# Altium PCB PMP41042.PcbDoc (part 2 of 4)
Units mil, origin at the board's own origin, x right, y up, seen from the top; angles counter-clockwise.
Board outline 9847.6 x 4445 mil, 6 copper layers (Top Layer, Layer 1, Layer 2, Layer 3, Layer 4, Bottom Layer), stack 32.112 mil thick; 329 components, 129 nets, 1246 pads, 863 vias.
Unrouted connection lines stored in the file: 6.

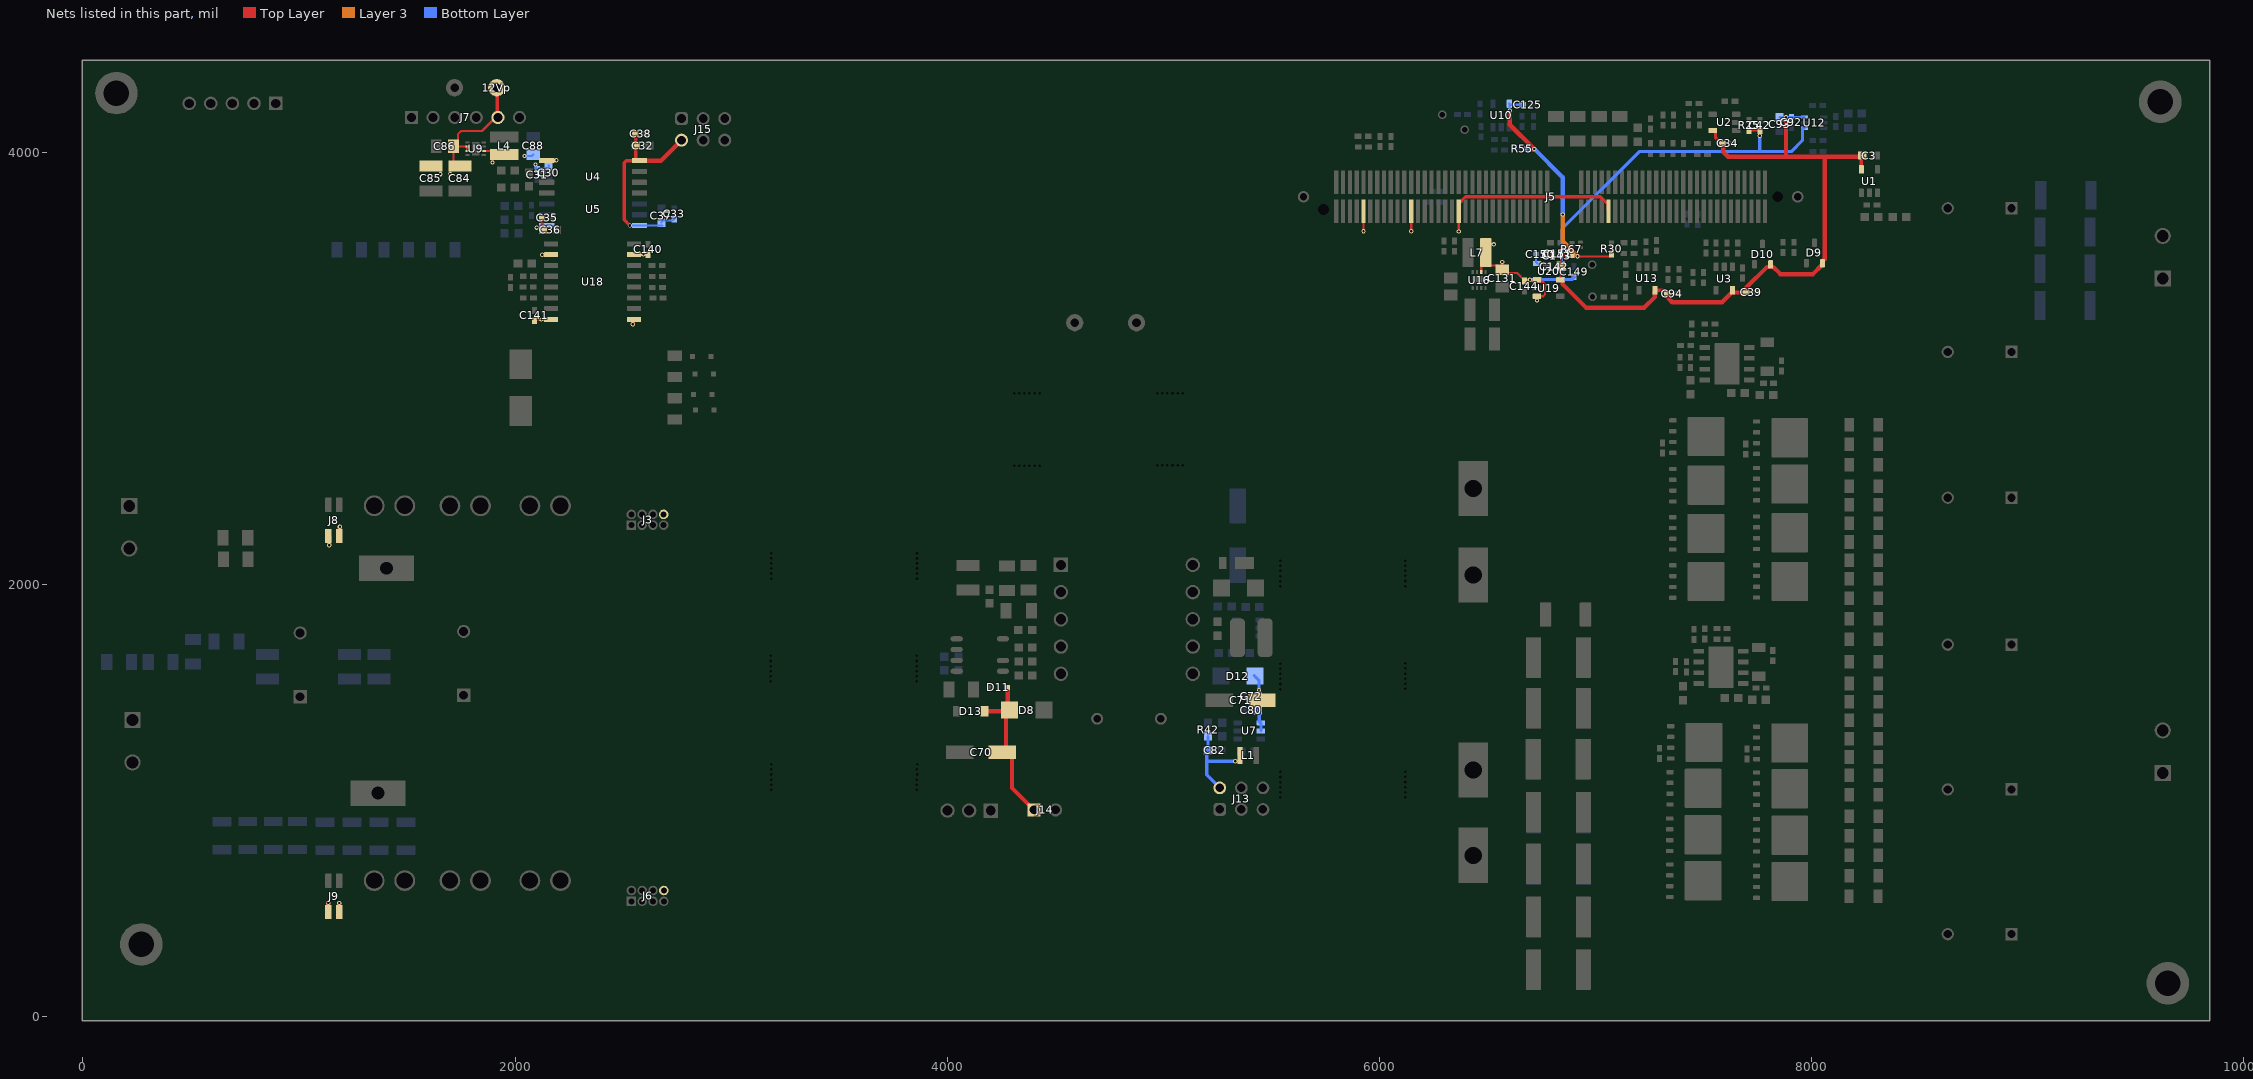
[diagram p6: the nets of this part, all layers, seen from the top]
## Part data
12Vp 12Vs: library part CMP-0055137-1, "Test Point, Miniature, Red, TH", Color=Red, Manufacturer=Keystone, Supplier Part Number 1=36-5000-ND
C1 C5 C9 C15 C90 C113 C118: library part CMP-0034099-1, "Cap Ceramic 10nF 1000V C0G 5% Pad SMD 1210 +125°C Automotive T/R", Manufacturer=TDK, Operating Temperature Range="-55°C to +125°C", TempCo=30ppm/°C, Temperature Characteristic=C0G, Tolerance_%=0.05%, ValueDisplayed=10nF
C2 C4 C6 C7 C10 C14 C16 C17 C19 C21 C23 C24 C27 C28: library part CMP-0097370-1, "0.3 µF ±5% 250V Ceramic Capacitor C0G, NP0 Stacked SMD, 2 J-Lead", Digikey Part Number=445-175448-1-ND, Manufacturer=TDK, Mouser Part Number=810-CKG57NCG2E304J50, Operating Temperature Range="-55°C to +125°C", TempCo=30ppm/°C, Temperature Characteristic=C0G, Tolerance_%=5%, ValueDisplayed=300nF
C3: library part CMP-0007378-5, "CAP, CERM, 0.1 uF, 16 V, +/- 10%, X7R, 0603", Cap_Case=0603, Manufacturer=MuRata, Supplier Part Number 1=490-1532-1-ND, TempCo=X7R, Tolerance_%=10%, Value1=Unknown, Value2=16V, ValueDisplayed=0.1uF
C8 C101: library part CMP-0009975-3, "CAP, AL, 150 uF, 450 V, +/- 20%, TH", Cap_Case=18x45mm, Manufacturer=Rubycon, Supplier Part Number 1=1189-1353-ND, Tolerance_%=20%, Value1=Unknown, Value2=450V, ValueDisplayed=150uF
C11 C12 C13: library part CMP-0009140-2, "CAP, CERM, 0.1 uF, 630 V, +/- 10%, X7R, AEC-Q200 Grade 1, 1210", Cap_Case=1210, Manufacturer=TDK, Supplier Part Number 1=445-7116-1-ND, TempCo=X7R, Tolerance_%=10%, Value1=Unknown, Value2=630V, ValueDisplayed=0.1uF
C18: library part CMP-0006470-1, "CAP, CERM, 470 pF, 50 V, +/- 5%, C0G/NP0, 0402", Cap_Case=0402, Manufacturer=MuRata, Supplier Part Number 1=490-1297-1-ND, TempCo=C0G/NP0, Tolerance_%=5%, Value1=Unknown, Value2=50V, ValueDisplayed=470pF
C20 C22: library part CMP-0097363-1, "Multilayer Ceramic Capacitors 100nF ±5% 250V C0G SMD 1812", Manufacturer=TDK, Operating Temperature Range="-55°C to +125°C", TempCo=30ppm/°C, Temperature Characteristic=C0G, Tolerance_%=0.05%, ValueDisplayed=100nF
C25 C42: library part CMP-0006352-2, "CAP, CERM, 0.01 uF, 25 V, +/- 10%, X7R, 0402", Cap_Case=0402, Manufacturer=MuRata, Supplier Part Number 1=490-6043-2-ND, TempCo=X7R, Tolerance_%=10%, Value1=Unknown, Value2=25V, ValueDisplayed=0.01uF
C26 C109 C139 C145 C146 C147 C148: library part CMP-0006408-1, "CAP, CERM, 10 pF, 50 V, +/- 5%, C0G/NP0, 0402", Cap_Case=0402, Manufacturer=MuRata, Supplier Part Number 1=81-GRM1555C1H100JA1D, TempCo=C0G/NP0, Tolerance_%=5%, Value1=Unknown, Value2=50V, ValueDisplayed=10pF
C29 C43 C45: library part CMP-0860554-1, "CAP, CERM, 0.01 µF, 16 V,+/- 10%, X7R, 0402", Cap_Case=0402, Manufacturer=Yageo, TempCo=X7R, Tolerance_%=10%, Value2=16V, ValueDisplayed=0.01µF
C30 C32 C93: library part CMP-0079607-1, "CAP, CERM, 1 µF, 16 V,+/- 10%, X7R, AEC-Q200 Grade 1, 0603", Cap_Case=0603, Manufacturer=TDK, Supplier Part Number 1=445-12539-1-ND, TempCo=X7R, Tolerance_%=10%, Value2=16V, ValueDisplayed=1µF
C31 C33 C34 C35 C38 C39 C92 C94 C103 C110 C112 C114 C125: library part CMP-0006659-2, "CAP, CERM, 0.1 uF, 25 V, +/- 10%, X7R, 0402", Cap_Case=0402, Manufacturer=MuRata, Supplier Part Number 1=490-10698-1-ND, TempCo=X7R, Tolerance_%=10%, Value1=Unknown, Value2=25V, ValueDisplayed=0.1uF
C36 C37 C102 C115: library part CMP-0064936-4, "CAP, CERM, 4.7 uF, 16 V,+/- 10%, X7R, 0603", Cap_Case=0603, Manufacturer=MuRata, TempCo=X7R, Tolerance_%=10%, Value1=Unknown, Value2=16V, ValueDisplayed=4.7uF
C40: library part CMP-0079721-1, "CAP, CERM, 0.01 µF, 25 V,+/- 10%, X7R, 0603", Cap_Case=0603, Manufacturer="Presidio Components", TempCo=X7R, Tolerance_%=10%, Value2=25V, ValueDisplayed=0.01µF
C41 C44 C46 C47 C48 C49 C50 C51 C52 C53 C54 C55 C56 C57 C60 C76 C77 C87 C163 C164 C186 C187 C188 C189 C190: library part CMP-0008971-1, "CAP, CERM, 2.2 uF, 100 V, +/- 10%, X7R, 1206_190", Cap_Case=1206, Manufacturer=MuRata, Supplier Part Number 1=490-7209-1-ND, TempCo=X7R, Tolerance_%=10%, Value1=Unknown, Value2=100V, ValueDisplayed=2.2uF
C58 C59 C61 C62 C63 C64: library part CMP-0097417-1, "1000 µF 80 V Aluminum Electrolytic Capacitors Radial, Can 27mOhm @ 100kHz 2000 Hrs @ 135°C", Digikey Part Number=565-EGPD800ELL102ML35H-ND, Leakage Current=2400uA, Manufacturer="United Chemi-Con", Mouser Part Number=661-EGPD800E102ML35H, Operating Temperature Range="-40°C to +135°C", Tolerance_%=20%, ValueDisplayed=1000uF
C65: library part CMP-0009608-4, "CAP, CERM, 47 pF, X1 250 VAC/Y1 300 VAC, +/- 10%, B, TH", Cap_Case=7x5x10mm, Manufacturer=MuRata, Supplier Part Number 1=490-9495-1-ND, TempCo=B, Tolerance_%=10%, Value1=Unknown, ValueDisplayed=47pF
C66: library part CMP-0008910-2, "CAP, CERM, 0.01 uF, 630 V, +/- 10%, X7R, 1206", Cap_Case=1206, Manufacturer=MuRata, Supplier Part Number 1=490-3512-1-ND, TempCo=X7R, Tolerance_%=10%, Value1=Unknown, Value2=630V, ValueDisplayed=0.01uF
C67: library part CMP-0009092-1, "CAP, CERM, 0.1 uF, 500 V, +/- 10%, X7R,", Cap_Case=1210, Manufacturer=Kemet, Supplier Part Number 1=399-6478-1-ND, TempCo=X7R, Tolerance_%=10%, Value1=Unknown, Value2=500V, ValueDisplayed=0.1uF
C68: library part CMP-0012117-3, "CAP, Aluminum Polymer, 100 uF, 25 V, +/- 20%, 0.024 ohm, 8.0x7.0mm SMD", Manufacturer=Panasonic, Tolerance_%=20%, Value1="0.024 ohm", Value2=25V, ValueDisplayed=100uF
C69 C72: library part CMP-0007404-4, "CAP, CERM, 0.1 uF, 25 V, +/- 10%, X7R, 0603", Cap_Case=0603, Manufacturer=MuRata, Supplier Part Number 1=490-16477-2-ND, TempCo=X7R, Tolerance_%=10%, Value1=Unknown, Value2=25V, ValueDisplayed=0.1uF
C70: library part CMP-0010738-1, "CAP, AL, 220 uF, 25 V, +/- 20%, 0.16 ohm, AEC-Q200 Grade 2, SMD", Cap_Case=6.3x7.7mm, Manufacturer=Panasonic, Supplier Part Number 1=PCE5009CT-ND, Tolerance_%=20%, Value1="0.16 ohm", Value2=25V, ValueDisplayed=220uF
C71: library part CMP-0084632-1, "CAP, AL, 470 µF, 10 V, +/- 20%, 0.16 ohm, AEC-Q200 Grade 2, SMD", Cap_Case=6.6x6.6x8mm, Manufacturer=Panasonic, Tolerance_%=20%, Value1="0.16 ohm", Value2=10V, ValueDisplayed=470µF
C73: library part CMP-0008646-2, "CAP, CERM, 47 uF, 25 V, +/- 20%, JB, 1206", Cap_Case=1206, Manufacturer=TDK, Supplier Part Number 1=445-11717-1-ND, TempCo=JB, Tolerance_%=20%, Value1=Unknown, Value2=25V, ValueDisplayed=47uF
C74: library part CMP-0006840-4, "CAP, CERM, 100 pF, 50 V, +/- 5%, C0G/NP0, 0603", Cap_Case=0603, Manufacturer=Kemet, Supplier Part Number 1=1414602, TempCo=C0G/NP0, Tolerance_%=5%, Value1=Unknown, Value2=50V, ValueDisplayed=100pF
C75: library part CMP-0007224-4, "CAP, CERM, 56 pF, 50 V, +/- 5%, C0G/NP0, 0603", Cap_Case=0603, Manufacturer=MuRata, Supplier Part Number 1=490-1421-1-ND, TempCo=C0G/NP0, Tolerance_%=5%, Value1=Unknown, Value2=50V, ValueDisplayed=56pF
C78 C79: library part CMP-0007039-5, "CAP, CERM, 0.1 uF, 25 V, +/- 10%, X7R, 0603", Cap_Case=0603, Manufacturer=TDK, Supplier Part Number 1=445-1316-1-ND, TempCo=X7R, Tolerance_%=10%, Value1=Unknown, Value2=25V, ValueDisplayed=0.1uF
C80 C81: library part CMP-0007347-1, "CAP, CERM, 4.7 uF, 25 V, +/- 10%, X5R, 0603", Cap_Case=0603, Manufacturer=MuRata, Supplier Part Number 1=490-7203-1-ND, TempCo=X5R, Tolerance_%=10%, Value1=Unknown, Value2=25V, ValueDisplayed=4.7uF
C82: library part CMP-0007005-1, "CAP, CERM, 22 uF, 10 V, +/- 20%, X5R, 0603", Cap_Case=0603, Manufacturer=TDK, Supplier Part Number 1=445-9077-1-ND, TempCo=X5R, Tolerance_%=20%, Value1="0.00371 ohm", Value2=10V, ValueDisplayed=22uF
C83: library part CMP-0007501-4, "CAP, CERM, 10 uF, 25 V, +/- 20%, X5R, 0603", Cap_Case=0603, Manufacturer=MuRata, Supplier Part Number 1=490-12323-1-ND, TempCo=X5R, Tolerance_%=20%, Value1=Unknown, Value2=25V, ValueDisplayed=10uF
C84 C85 C128 C129: library part CMP-0009211-2, "CAP, CERM, 47 uF, 16 V, +/- 10%, X5R, 1210", Cap_Case=1210, Manufacturer=MuRata, Supplier Part Number 1=GRM32ER61C476KE15L-ND, TempCo=X5R, Tolerance_%=10%, Value1=Unknown, Value2=16V, ValueDisplayed=47uF
C86 C130: library part CMP-0007728-2, "CAP, CERM, 1 uF, 25 V, +/- 10%, X7R, 0805", Cap_Case=0805, Manufacturer=Kemet, Supplier Part Number 1=399-8004-1-ND, TempCo=X7R, Tolerance_%=10%, Value1=Unknown, Value2=25V, ValueDisplayed=1uF
C88 C131: library part CMP-0085852-1, "CAP, CERM, 22 µF, 16 V,+/- 10%, X5R, 0805", Cap_Case=0805, Manufacturer="Samsung Electro-Mechanics", TempCo=X5R, Tolerance_%=10%, Value2=16V, ValueDisplayed=22µF
C89 C104 C117 C133: library part CMP-0006201-2, "CAP, CERM, 0.1 uF, 16 V, +/- 10%, X7R, 0402", Cap_Case=0402, Manufacturer=AVX, Supplier Part Number 1=478-7888-1-ND, TempCo=X7R, Tolerance_%=10%, Value1=Unknown, Value2=16V, ValueDisplayed=0.1uF
C91 C124: library part CMP-0006448-1, "CAP, CERM, 2.2 pF, 50 V, +/- 5%, C0G/NP0, 0402", Cap_Case=0402, Manufacturer=MuRata, Supplier Part Number 1=81-GRM1555C1H2R2CA1D, TempCo=C0G/NP0, Tolerance_%=5%, Value1=Unknown, Value2=50V, ValueDisplayed=2.2pF
C95 C132: library part CMP-0860561-1, "CAP, CERM, 0.01 µF, 25 V,+/- 10%, X7R, 0402", Cap_Case=0402, Manufacturer="Samsung Electro-Mechanics", TempCo=X7R, Tolerance_%=10%, Value2=25V, ValueDisplayed=0.01µF
C96: library part CMP-0006666-2, "CAP, CERM, 0.033 uF, 25 V, +/- 10%, X7R, 0402", Cap_Case=0402, Manufacturer=MuRata, Supplier Part Number 1=490-3253-1-ND, TempCo=X7R, Tolerance_%=10%, Value1=Unknown, Value2=25V, ValueDisplayed=0.033uF
C97: library part CMP-0006320-2, "CAP, CERM, 470 pF, 50 V, +/- 10%, X7R, AEC-Q200 Grade 1, 0402", Cap_Case=0402, Manufacturer=TDK, Supplier Part Number 1=445-6888-1-ND, TempCo=X7R, Tolerance_%=10%, Value1="4.96489 ohm", Value2=50V, ValueDisplayed=470pF
C98 C107 C108 C116 C122 C123 C126 C127 C134 C135: library part CMP-0006233-1, "CAP, CERM, 100 pF, 25 V, +/- 5%, C0G/NP0, 0402", Cap_Case=0402, Manufacturer=Kemet, Supplier Part Number 1=399-1022-1-ND, TempCo=C0G/NP0, Tolerance_%=5%, Value1=Unknown, Value2=25V, ValueDisplayed=100pF
C99 C100 C111: library part CMP-0860560-1, "CAP, CERM, 1000 pF, 50 V,+/- 10%, X7R, 0402", Cap_Case=0402, Manufacturer="Samsung Electro-Mechanics", TempCo=X7R, Tolerance_%=10%, Value2=50V, ValueDisplayed=1000pF
C105 C120: library part CMP-0078499-1, "CAP, CERM, 4.7 µF, 100 V,+/- 20%, X7S, 1206", Cap_Case=1206, Manufacturer=AVX, Supplier Part Number 1=478-8719-1-ND, TempCo=X7S, Tolerance_%=20%, Value2=100V, ValueDisplayed=4.7µF
C106 C121: library part CMP-0006618-1, "CAP, CERM, 0.1 uF, 100 V, +/- 10%, X5R, 0402", Cap_Case=0402, Manufacturer=MuRata, Supplier Part Number 1=490-10458-1-ND, TempCo=X5R, Tolerance_%=10%, Value1=Unknown, Value2=100V, ValueDisplayed=0.1uF
C119: library part CMP-0034099-1, "Cap Ceramic 18nF 1000V C0G 5% Pad SMD 1210 +125°C Automotive T/R", Manufacturer=TDK, Operating Temperature Range="-55°C to +125°C", Part Number=CGA6P1C0G3A103J250AC, TempCo=30ppm/°C, Temperature Characteristic=C0G, Tolerance_%=0.05%, ValueDisplayed=10nF
C140 C141: library part CMP-0006297-2, "CAP, CERM, 0.1 uF, 50 V, +/- 10%, X7R, 0402", Alternate Manufacturer="Wurth Elektronik", Alternate PartNumber=885012205037, Cap_Case=0402, Manufacturer=TDK, Supplier Part Number 1=445-5932-1-ND, TempCo=X7R, Tolerance_%=10%, Value1="0.039064 ohm", Value2=50V, ValueDisplayed=0.1uF
C142: library part CMP-0007365-1, "CAP, CERM, 1 uF, 10 V, +/- 10%, X7R, 0603", Cap_Case=0603, Manufacturer=MuRata, Supplier Part Number 1=490-3899-1-ND, TempCo=X7R, Tolerance_%=10%, Value1="0.011 ohm", Value2=10V, ValueDisplayed=1uF
C143 C150 C151: library part GRM155R70J104KA01D, "CAP, CERM, 0.1uF, 6.3V, +/-10%, X7R, 0402", Cap_Case=0402, Manufacturer=Yageo, TempCo=X7R, Tolerance_%=10, Value1=Unknown, Value2=6.3V, ValueDisplayed=0.1uF
C144 C149: library part CMP-0080610-1, "CAP, CERM, 0.1 µF, 25 V,+/- 10%, X7R, AEC-Q200 Grade 1, 0402", Cap_Case=0402, Manufacturer=TDK, Supplier Part Number 1=445-6902-1-ND, TempCo=X7R, Tolerance_%=10%, Value2=25V, ValueDisplayed=0.1µF
D1 D2 D3 D4: library part CMP-0029006-2, "Diode, Ultrafast, 100 V, 0.25 A, SOD-323", Manufacturer=Nexperia, Value1=0.25A, Value2=1.4V
D5: library part CMP-0028371-1, "Diode, Schottky, 100 V, 1 A, SMA", Manufacturer="Diodes Inc.", Supplier Part Number 1=B1100-FDICT-ND, Value1=1A, Value2=0.79V
D6: library part CMP-0077074-2, "Diode, Superfast Rectifier, 600 V, 1 A, 3.5x1.6mm", Manufacturer=Toshiba, Value1=1A, Value2=1.7V
D7: library part CMP-0005415-4, "Diode, Zener, 24 V, 1 W, PowerDI123", Manufacturer="Diodes Inc.", Power_W=1W
D8: library part CMP-0028391-2, "Diode, Schottky, 70 V, 1 A, SMA", Manufacturer="Diodes Inc.", Value1=1A, Value2=0.79V
D9 D10: library part CMP-0028456-1, "Diode, Schottky, 30 V, 0.2 A, SOT-23", Manufacturer="Diodes Inc.", Supplier Part Number 1=BAT54S-FDICT-ND, Value1=0.2A, Value2=0.65V
D11: library part CMP-0029006-1, "Diode, Ultrafast, 100 V, 0.25 A, SOD-323", Manufacturer=Nexperia, Supplier Part Number 1=568-5003-1-ND, Value1=0.25A, Value2=1.4V
D12: library part CMP-0028405-2, "Diode, Schottky, 50 V, 2 A, SMA", Manufacturer="Diodes Inc.", Value1=2A, Value2=0.7V
D13: library part CMP-0005747-4, "Diode, Zener, 18 V, 700 mW, SOD-123", Manufacturer=Toshiba, Power_W=700mW, Value1=0.7W
DGND PGND: library part CMP-0055138-1, "Test Point, Miniature, Black, TH", Color=Black, Manufacturer=Keystone, Supplier Part Number 1=36-5001-ND
GaN_SW1 GaN_SW1 GaN_SW2 GaN_SW2 HVBUS HVBUS HVBUS1 HVBUS2 PGND PGND PGND1 PGND2: library part CMP-0055026-1, Manufacturer=Mill-Max, Supplier Part Number 1=0312-015153427100-ND
J1 J2 J10 J11: library part CMP-0054978-1, "Therminal Block, 5 mm, 2-pole, Tin, TH", Manufacturer="TE Connectivity", Supplier Part Number 1=A98355-ND
J3 J6: library part CMP-0097755-1, "Conn Socket Strip SKT 8 POS 1.27mm Solder ST Thru-Hole", Current_A=1A, Manufacturer=Harwin, Operating Temperature Range="-40°C to +105°C"
J4: library part CMP-0054800-1, "Header, 2.54 mm, 5x1, Gold, R/A, TH", Color=Black, Manufacturer="Wurth Elektronik", Supplier Part Number 1=732-5338-ND
J5: library part CMP-0003814-2, "C2000 controlCARD-120HSEC connector, SMT", Manufacturer=Samtec
J7: library part CMP-0075621-1, "Receptacle, 6x1, 2.54mm, Tin, TH", Color=Black, Current_A=5.7A, Manufacturer=Samtec, Supplier Part Number 1=SAM1213-06-ND
J8 J9: library part CMP-0097647-1, Current_A=2.9A, Digikey Part Number=SAM1226-02-ND, Manufacturer=Samtec, Mouser Part Number=200-FLE10201GDV, Octopart Part Number=93aa5aa4310c4c6d, Operating Temperature Range="-55°C to +125°C"
J12: library part CMP-0054704-1, "Header, 100mil, 3x1, Tin, R/A, TH", Color=Black, Current_A=3A, Manufacturer="Sullins Connector Solutions", Supplier Part Number 1=S1112E-03-ND, Voltage_V=1.8kV
J13: library part CMP-0077741-2, "Header, 2.54mm, 3x2, Gold, R/A, TH", Color=Black, Current_A=3A, Manufacturer=Molex, Supplier Part Number 1=WM50030-06-ND, Voltage_V=350V
J14: library part CMP-0054712-1, "Header, 2.54 mm, 2x1, Tin, R/A, TH", Color=Black, Current_A=3A, Manufacturer="Sullins Connector Solutions", Supplier Part Number 1=S1112E-02-ND, Voltage_V=1.8kV
J15: library part CMP-0082513-1, "Receptacle, 2.54mm, 3x2, Gold, TH", Color=Black, Current_A=3A, Manufacturer="Sullins Connector Solutions", Supplier Part Number 1=S7106-ND, Voltage_V=250V
L1: library part CMP-0063086-1, "Inductor, Wirewound, Ferrite, 10 uH, 0.68 A, 0.46 ohm, SMD", Manufacturer="Würth Elektronik", Value1="0.843 ohm", Value2=0.6A, ValueDisplayed=10uH
L3: library part CMP-0064687-1, "Inductor, Wirewound, Ferrite, 18 uH, 1.1 A, 0.225 ohm, AEC-Q200 Grade 1, SMD", Manufacturer="Wurth Elektronik", Supplier Part Number 1=732-6815-1-ND, Value1="0.225 ohm", Value2=1.1A, ValueDisplayed=18uH
L4 L7: library part CMP-0087867-1, "2.2µH Shielded Molded Inductor 2.4A 67mOhm Max 2-SMD", Manufacturer="Wurth Electronics"
Q1 Q2 Q3 Q4 Q5 Q6 Q7 Q8 Q9 Q10 Q11 Q12 Q13 Q14 Q15 Q16: library part CMP-0000915-1, "MOSFET, N-CH, 80 V, 100 A, DNK0008A (VSON-CLIP-8)", Alternate Manufacturer=None, Manufacturer="Texas Instruments", Supplier Part Number 1=296-37194-1-ND, Value2="48 nC"
R1 R2 R4 R7: library part CMP-0016568-2, "RES, 100 k, 1%, 0.25 W, 1206", Manufacturer=Vishay-Dale, Power_W=250mW, Supplier Part Number 1=541-100KFCT-ND, TempCo="100 ppm/C", Tolerance_%=1%, Value2=0.25W, Value_Code=100k
R3: library part CMP-0022438-1, "RES, 47.0 k, 1%, 0.1 W, AEC-Q200 Grade 0, 0603", Manufacturer=Vishay-Dale, Power_W=100mW, Supplier Part Number 1=541-47.0KHCT-ND, TempCo="100 ppm/C", Tolerance_%=1%, Value2=0.1W, Value_Code=47k0, ValueDisplayed=47.0k
R5 R27: library part CMP-0022983-5, "RES, 2.10 k, 1%, 0.1 W, 0603", Manufacturer=Yageo, Power_W=100mW, Supplier Part Number 1=311-2.10KHRCT-ND, TempCo="100 ppm/C", Tolerance_%=1%, Value2=0.1W, Value_Code=2k10, ValueDisplayed=2.10k
R6 R74: library part CMP-0025884-2, "RES, 0, 5%, 0.125 W, 0603", Manufacturer=Vishay/Beyschlag, Power_W=125mW, Supplier Part Number 1=MCT0603-0.0-ZZCT-ND, TempCo=ppm/C, Tolerance_%=5%, Value2=0.125W, Value_Code=0000, ValueDisplayed=0
R8 R9: library part CMP-0078823-1, "RES, 0.004, 1%, 1 W, AEC-Q200 Grade 0, 1206", Manufacturer=Bourns, Power_W=1W, TempCo="50 ppm/C", Tolerance_%=1%, Value_Code=4L000, ValueDisplayed=0.004
R10 R11 R12 R13: library part CMP-0018320-1, "RES, 47.0, 1%, 0.25 W, 1206", Manufacturer="Yageo America", Power_W=250mW, Supplier Part Number 1=311-47.0FRCT-ND, TempCo="100 ppm/C", Tolerance_%=1%, Value2=0.25W, Value_Code=47R0, ValueDisplayed=47.0
R14 R19 R21 R25: library part CMP-0026739-1, "RES, 4.70 k, 1%, 0.0625 W, 0402", Manufacturer="Yageo America", Power_W=62.5mW, Supplier Part Number 1=311-4.7KLRCT-ND, TempCo="100 ppm/C", Tolerance_%=1%, Value2=0.0625W, Value_Code=4k70, ValueDisplayed=4.70k
R15 R17: library part CMP-0017437-1, "RES, 200 k, 1%, 0.25 W, 1206", Manufacturer=Panasonic, Power_W=250mW, Supplier Part Number 1=P200KFCT-ND, TempCo="100 ppm/C", Tolerance_%=1%, Value2=0.25W, Value_Code=200k
R16 R29: library part CMP-0026769-2, "RES, 10.0 k, 0.5%, 0.063 W, AEC-Q200 Grade 0, 0402", Manufacturer=Vishay-Dale, Power_W=63mW, Supplier Part Number 1=541-10KAVCT-ND, TempCo="50 ppm/C", Tolerance_%=0.5%, Value2=0.063W, Value_Code=10k0, ValueDisplayed=10.0k
R18 R24 R70 R72: library part CMP-0022003-4, "RES, 10.0, 1%, 0.1 W, AEC-Q200 Grade 0, 0603", Manufacturer=Vishay-Dale, Power_W=100mW, Supplier Part Number 1=541-10.0HCT-ND, TempCo="100 ppm/C", Tolerance_%=1%, Value2=0.1W, Value_Code=10R0, ValueDisplayed=10.0
R20: library part CMP-0017285-1, "RES, 100 k, 1%, 0.25 W, 1206", Manufacturer=Panasonic, Power_W=250mW, Supplier Part Number 1=P100KFCT-ND, TempCo="100 ppm/C", Tolerance_%=1%, Value2=0.25W, Value_Code=100k
R22 R28: library part CMP-0025697-2, "RES, 0, 5%, 0.1 W, 0603", Manufacturer=Vishay-Dale, Power_W=100mW, Supplier Part Number 1=541-0.0GCT-ND, TempCo="200 ppm/C", Tolerance_%=5%, Value2=0.1W, Value_Code=0000, ValueDisplayed=0
R23 R26: library part CMP-0026514-2, "RES, 6.34 k, 1%, 0.063 W, AEC-Q200 Grade 0, 0402", Manufacturer=Vishay-Dale, Power_W=63mW, Supplier Part Number 1=541-6.34KLCT-ND, TempCo="100 ppm/C", Tolerance_%=1%, Value2=0.063W, Value_Code=6k34, ValueDisplayed=6.34k
R30 R31 R55 R58: library part CMP-0025958-1, "RES, 10.0 k, 1%, 0.063 W, 0402", Manufacturer=Vishay-Dale, Power_W=63mW, Supplier Part Number 1=541-10.0KLCT-ND, TempCo="100 ppm/C", Tolerance_%=1%, Value2=0.063W, Value_Code=10k0, ValueDisplayed=10.0k
R32: library part CMP-0018591-3, "RES, 150 k, 5%, 0.25 W, 1206", Manufacturer=Vishay-Dale, Power_W=250mW, Supplier Part Number 1=541-150KECT-ND, TempCo="200 ppm/C", Tolerance_%=5%, Value2=0.25W, Value_Code=150k
R33: library part CMP-0025720-4, "RES, 15, 5%, 0.1 W, AEC-Q200 Grade 0, 0603", Manufacturer=Vishay-Dale, Power_W=100mW, Supplier Part Number 1=541-15GCT-ND, TempCo="200 ppm/C", Tolerance_%=5%, Value2=0.1W, Value_Code=15R0, ValueDisplayed=15
R34: library part CMP-0023166-5, "RES, 51.1 k, 1%, 0.1 W, 0603", Manufacturer=Yageo, Power_W=100mW, Supplier Part Number 1=311-51.1KHRCT-ND, TempCo="100 ppm/C", Tolerance_%=1%, Value2=0.1W, Value_Code=51k1, ValueDisplayed=51.1k
R35: library part CMP-0025885-5, "RES, 0, 5%, 0.1 W, 0603", Manufacturer=Yageo, Power_W=100mW, Supplier Part Number 1=311-0.0GRCT-ND, TempCo="200 ppm/C", Tolerance_%=5%, Value2=0.1W, Value_Code=0000, ValueDisplayed=0
R36 R37 R47 R48: library part CMP-0022711-2, "RES, 2.20, 1%, 0.1 W, 0603", Manufacturer=Vishay-Dale, Power_W=100mW, Supplier Part Number 1=541-5.1GCT-ND, TempCo="200 ppm/C", Tolerance_%=5%, Value2=0.1W, Value_Code=5R10, ValueDisplayed=5.1
R38 R39 R51 R52: library part CMP-0026659-1, "RES, 100 k, 1%, 0.1 W, 0402", Manufacturer=Panasonic, Power_W=100mW, TempCo="100 ppm/C", Tolerance_%=1%, Value2=0.1W, Value_Code=100k
R40: library part CMP-0022945-5, "RES, 24.0 k, 1%, 0.1 W, 0603", Manufacturer=Yageo, Power_W=100mW, Supplier Part Number 1=311-24.0KHRCT-ND, TempCo="100 ppm/C", Tolerance_%=1%, Value2=0.1W, Value_Code=24k0, ValueDisplayed=24.0k
R41: library part CMP-0025080-1, "RES, 2.00 k, 0.5%, 0.1 W, 0603", Manufacturer="Yageo America", Power_W=100mW, TempCo="50 ppm/C", Tolerance_%=0.5%, Value2=0.1W, Value_Code=2k00, ValueDisplayed=2.00k
R42: library part CMP-0022632-1, "RES, 88.7 k, 1%, 0.1 W, 0603", Manufacturer=Vishay-Dale, Power_W=100mW, Supplier Part Number 1=541-88.7KHCT-ND, TempCo="100 ppm/C", Tolerance_%=1%, Value2=0.1W, Value_Code=88k7, ValueDisplayed=88.7k
R43: library part CMP-0023982-2, "RES, 243 k, 0.1%, 0.1 W, 0603", Manufacturer="Yageo America", Power_W=100mW, TempCo="25 ppm/C", Tolerance_%=0.1%, Value2=0.1W, Value_Code=243k
R44 R45: library part CMP-0022220-1, "RES, 22.1 k, 1%, 0.1 W, 0603", Manufacturer=Vishay-Dale, Power_W=100mW, Supplier Part Number 1=541-22.1KHCT-ND, TempCo="100 ppm/C", Tolerance_%=1%, Value2=0.1W, Value_Code=22k1, ValueDisplayed=22.1k
R46 R49 R50 R54: library part CMP-0015817-2, "RES, 0.0005, 1%, 2 W, 2512", Manufacturer="Stackpole Electronics Inc", Power_W=3W, TempCo=ppm/C, Tolerance_%=1%, Value2=2W, Value_Code=1L000, ValueDisplayed=0.0005
R53: library part CMP-0026883-3, "RES, 24 k, 5%, 0.063 W, AEC-Q200 Grade 0, 0402", Manufacturer=Vishay-Dale, Power_W=63mW, Supplier Part Number 1=541-10.0KLCT-ND, TempCo="100 ppm/C", Tolerance_%=1%, Value2=0.063W, Value_Code=10k0, ValueDisplayed=10.0k
R56 R66: library part CMP-0026657-1, "RES, 1.00 k, 1%, 0.1 W, 0402", Manufacturer=Panasonic, PartNumber=ERJ-2RKF1001X, Power_W=100mW, Supplier Part Number 1=P1.00KLCT-ND, TempCo="100 ppm/C", Tolerance_%=1%, Value2=0.1W, Value_Code=1k00, ValueDisplayed=1.00k
R57 R68: library part CMP-0026657-1, "RES, 1.00 k, 1%, 0.1 W, 0402", Manufacturer=Panasonic, Power_W=100mW, Supplier Part Number 1=P1.00KLCT-ND, TempCo="100 ppm/C", Tolerance_%=1%, Value2=0.1W, Value_Code=1k00, ValueDisplayed=1.00k
R59 R76 R84 R85 R86 R89 R97 R98 R101 R102 R103 R104 R105 R106: library part CMP-0025951-1, "RES, 100, 1%, 0.063 W, 0402", Manufacturer=Vishay-Dale, Power_W=63mW, Supplier Part Number 1=541-100LCT-ND, TempCo="100 ppm/C", Tolerance_%=1%, Value2=0.063W, Value_Code=100R, ValueDisplayed=100
R64: library part CMP-0025958-1, "RES, 10.0 k, 1%, 0.063 W, 0402", Manufacturer=Vishay-Dale, Power_W=63mW, Supplier Part Number 1=541-3.6KJCT-ND, TempCo="200 ppm/C", Tolerance_%=5%, Value2=0.063W, Value_Code=3k60, ValueDisplayed=3.6k
R67: library part CMP-0025958-3, "RES, 10.0 k, 1%, 0.063 W, AEC-Q200 Grade 0, 0402", Manufacturer=Vishay-Dale, PartNumber=CRCW040210K0FKED, Power_W=63mW, Supplier Part Number 1=541-10.0KLCT-ND, TempCo="100 ppm/C", Tolerance_%=1%, Value2=0.063W, Value_Code=10k0, ValueDisplayed=10.0k
R77 R78 R90 R91: library part CMP-0025963-3, "RES, 10.0, 1%, 0.063 W, AEC-Q200 Grade 0, 0402", Manufacturer=Vishay-Dale, Power_W=63mW, Supplier Part Number 1=541-10.0LCT-ND, TempCo="100 ppm/C", Tolerance_%=1%, Value2=0.063W, Value_Code=10R0, ValueDisplayed=10.0
R79 R82 R92 R93: library part CMP-0025958-2, "RES, 10.0 k, 1%, 0.063 W, 0402", Manufacturer=Vishay-Dale, Power_W=63mW, Supplier Part Number 1=541-10.0KLCT-ND, TempCo="100 ppm/C", Tolerance_%=1%, Value2=0.063W, Value_Code=10k0, ValueDisplayed=10.0k
R81 R83: library part CMP-0026904-3, "RES, 30, 5%, 0.063 W, AEC-Q200 Grade 0, 0402", Manufacturer=Vishay-Dale, Power_W=63mW, Supplier Part Number 1=541-30JCT-ND, TempCo="200 ppm/C", Tolerance_%=5%, Value2=0.063W, Value_Code=30R0, ValueDisplayed=30
RT1: library part CMP-0084566-1, "Thermistor, DEC0002A (X1SON-2)", Alternate Manufacturer="Texas Instruments", Alternate PartNumber=TMP6131DECT
T2: library part CMP-0097353-1, "50 A 1:150 Current Sense Transformer 20kHz ~ 1MHz 0.5mOhm Primary, 6Ohm Secondary Max 10 mH Surface Mount", Digikey Part Number=553-PAS6322.150NLTCT-ND, Frequency_Fixed=50-1000kHz, Manufacturer=Pulse, Mouser Part Number=673-PAS6322.150NLT, Operating Temperature Range="-40°C to +130°C", Voltage_Isolation_Vrms=3500Vrms
T3: library part "Trans BB", "flyback transformer for UCC28911 dual output", Manufacturer="Wurth Elektronik"
U1 U2 U3: library part CMP-0040888-1, "Precision, 20 MHz, 0.9 pA Ib, RRIO, CMOS Operational Amplifier, 1.8 to 5.5 V, -40 to 125 degC, 5-pin SOT23 (DBV5), Green (RoHS & no Sb/Br)", Manufacturer="Texas Instruments", Total Supply Voltage(Max)(+5V is 5, +/-5V is 10)=5.5, Total Supply Voltage(Min)(+5V is 5, +/-5V is 10)=1.8
U4: library part CMP-0080587-1, "Precision Reinforced Isolated Amplifier for Current Sensing, DWV0008A (SOIC-8)", Alternate Manufacturer="Texas Instruments"
U5: library part CMP-0078341-1, "Precision, 2-V Input, Reinforced Isolated Amplifier, DWV0008A (SOIC-8)", Alternate Manufacturer="Texas Instruments", Alternate PartNumber=AMC1311BDWV
U6: library part CMP-0074093-2, "700V Flyback Switcher with Constant-Voltage Constant-Current and Primary-side Regulation, D0007A (SOIC-7)", Alternate Manufacturer="Texas Instruments", Alternate PartNumber=UCC28911D
U7 U8: library part CMP-0065097-1, "4V to 36 V 0.6 A Synchronous Step-Down Converter, DBV0006A (SOT-23-6)", Alternate Manufacturer="Texas Instruments", Alternate PartNumber=TPS560430XDBVT
U9 U16: library part CMP-0037791-2, "Buck Step Down Regulator with 3 to 17 V Input and 5 V Output, -40 to 85 degC, 8-Pin WSON (DSG), Green (RoHS & no Sb/Br)", Manufacturer="Texas Instruments", Rating=Catalog, Switch Current Limit(Typ)(A)=1.8
U10 U13: library part CMP-0068461-1, "Low Voltage, 45MHz, Rail-to-Rail Output Operational Amplifiers with Shutdown Option, 5-pin SOT-23, Pb-Free", Manufacturer="Texas Instruments", Package Reference=DBV0005A, PackageTopMarking=AC1A*XTT, PowerWise=N
U12: library part CMP-0077332-3, "26-V, Bi-Directional, Zero-Drift, High Accuracy, Low-/High-Side, Voltage Out Current Shunt Monitor, DCK0006A (SOT-SC70-6)", Alternate Manufacturer="Texas Instruments", Alternate PartNumber=INA214AIDCKT, Operating Temperature Range="-40 to 125 C", Rating=Catalog
U14 U15: library part CMP-0073887-2, "120-V Boot, 4-A Peak, High-Frequency High-Side and Low-Side Driver, DDA0008E (SOIC-8)", Alternate Manufacturer="Texas Instruments"
U18: library part CMP-0076066-3, "Automotive, High Speed, Robust EMC Quad-Channel Digital Isolators, DW0016B (SOIC-16)", Alternate Manufacturer="Texas Instruments", Alternate PartNumber=ISO7742FQDWQ1, Operating Temperature Range="-40 to 125 C", Rating=Automotive
U19: library part CMP-0073750-1, "Capacitor-Free, 150-mA, LDO Regulator w/ Foldback Current Limit, DBV0005A (SOT-23-5)", Alternate Manufacturer="Texas Instruments"
U20: library part CMP-0066190-1, "Low-Drift, Low-Power, Dual-Output VREF and VREF/2 Voltage Reference, DDC0005A (SOT-23-T-5)", Alternate Manufacturer="Texas Instruments", Alternate PartNumber=REF2033AIDDCT

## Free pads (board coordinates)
  round 40 hole 25: 1(6292,4175) 1(6395,4106) 1(6985,3481) 1(6987,3333)
  rect 255.91x118.11 hole 59.06 slot 196.85 at 0 deg: 2(1365.35,1035) 2(1405,2075.63)
  rect 137.8x255.91 hole 78.74 slot 196.85 at 90 deg: 2(6435,746.89) 2(6435,1141.73) 2(6435,2045) 2(6435,2445)
  round 196.85 hole 118.11: 3(155,4275) 3(270,335) 3(9615,4235) 3(9650,155)
  round 0 hole 11.81 unplated: 4(3183.6,1552.01) 4(3185,2028) 4(3185.09,1050.24) 4(3859,1552) 4(3860,1050) 4(3860.4,2027.99) 4(4309.89,2551) 4(4310,2885) 4(4971.99,2551.6) 4(4972.1,2885.6) 4(5541.99,1015.08) 4(5541.99,1516.57) 4(5541.99,1992.57) 4(6119.99,1015.57) 4(6119.99,1517.57) 4(6119.99,1993.33) 14(3183.6,1552.01) 14(3185,2028) 14(3185.09,1050.24) 14(3859,1552) 14(3860,1050) 14(3860.4,2027.99) 14(4309.89,2551) 14(4310,2885) 14(4971.99,2551.6) 14(4972.1,2885.6) 14(5541.99,1015.08) 14(5541.99,1516.57) 14(5541.99,1992.57) 14(6119.99,1015.57) 14(6119.99,1517.57) 14(6119.99,1993.33) 15(3183.6,1575.64) 15(3185,2051.62) 15(3185.09,1073.86) 15(3859,1575.62) 15(3860,1074) 15(3860.4,2051.61) 15(4333.51,2551) 15(4333.62,2885) 15(4995.61,2551.6) 15(4995.72,2885.6) 15(5541.99,1038.71) 15(5541.99,1540.19) 15(5541.99,2016.2) 15(6119.99,1039.19) 15(6119.99,1541.19) 15(6119.99,2016.95) 16(3183.6,1599.26) 16(3185,2075.24) 16(3185.09,1097.48) 16(3859,1599.24) 16(3860,1097) 16(3860.4,2075.23) 16(4357.13,2551) 16(4357.24,2885) 16(5019.23,2551.6) 16(5019.34,2885.6) 16(5541.99,1062.33) 16(5541.99,1563.82) 16(5541.99,2039.82) 16(6119.99,1062.82) 16(6119.99,1564.82) 16(6119.99,2040.57) 17(3183.6,1622.88) 17(3185,2098.87) 17(3185.09,1121.11) 17(3859,1622.87) 17(3860.4,2098.85) 17(3860.49,1121.09) 17(4380.76,2551) 17(4380.87,2885) 17(5042.85,2551.6) 17(5042.96,2885.6) 17(5541.99,1085.95) 17(5541.99,1587.44) 17(5541.99,2063.44) 17(6119.99,1086.44) 17(6119.99,1588.44) 17(6119.99,2064.2) 18(3183.6,1646.5) 18(3185,2122.49) 18(3185.09,1144.73) 18(3859,1646.49) 18(3860,1145) 18(3860.4,2122.47) 18(4404.38,2551) 18(4404.49,2885) 18(5066.47,2551.6) 18(5066.59,2885.6) 18(5541.99,1109.57) 18(5541.99,1611.06) 18(5541.99,2087.06) 18(6119.99,1110.06) 18(6119.99,1612.06) 18(6119.99,2087.82) 19(3183.6,1670.12) 19(3185,2146.11) 19(3185.09,1168.35) 19(3859,1670.11) 19(3860.4,2146.1) 19(3860.49,1168.34) 19(4428,2551) 19(4428.11,2885) 19(5090.1,2551.6) 19(5090.21,2885.6) 19(5541.99,1133.19) 19(5541.99,1634.68) 19(5541.99,2110.68) 19(6119.99,1133.68) 19(6119.99,1635.68) 19(6119.99,2111.44)

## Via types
v1: diameter 19.68, hole 10, Top Layer to Bottom Layer, tented both sides, 821 vias
v2: diameter 19.68, hole 7.87, Top Layer to Bottom Layer, 12 vias
v3: diameter 19.68, hole 12, Top Layer to Bottom Layer, tented both sides, 11 vias
v4: diameter 20, hole 10, Top Layer to Bottom Layer, tented both sides, 11 vias
v5: diameter 19.68, hole 7.87, Top Layer to Bottom Layer, tented both sides, 8 vias

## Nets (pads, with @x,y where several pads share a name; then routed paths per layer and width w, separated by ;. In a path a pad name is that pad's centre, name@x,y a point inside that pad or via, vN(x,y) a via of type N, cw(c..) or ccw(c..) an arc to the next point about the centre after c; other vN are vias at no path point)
1V65: C42.2 C151.1 R25.1 U12.1 U20.1 | length 1660.2
  Top Layer w10: R25.1@7711.5,4102.44 C42.2@7761.5,4102.44 7761.25,4102.19 7761.25,4078.25 v1(7761,4078)
  Bottom Layer w10: U20.1@6839.76,3487.28 6845.87,3493.39 C151.1@6845.87,3532.28
  Bottom Layer w15: C151.1@6845.87,3532.28 6845.87,3646.65 7203.66,4004.45 7765,4004.45 ; v1(7761,4078) 7761,4008.45 7765,4004.45 ; U12.1@7968.43,4113.22 7959.57,4113.22 7959.19,4112.85 7959.19,4103.99 7959,4103.8 7959,4057 7906.45,4004.45 7765,4004.45
3.3Vref: C150.1 U20.5 | length 44.4
  Bottom Layer w10: C150.1@6725.16,3529.09 6725.16,3493.62 U20.5@6731.5,3487.28
3.3Vs: C3.1 C34.1 C39.1 C92.2 C93.2 C94.2 C125.2 C142.1 C143.1 D9.2 D10.2 R30.2 R55.2 R67.1 U1.5 U2.5 U3.5 U10.5 U12.3 U13.5 U19.5 | length 4401.4
  Top Layer w10: U19.5@6838.23,3409.69 6838.23,3469.92 C142.1@6840.59,3472.28 6840.87,3472.56 C143.1@6840.87,3522.28 6886.24,3522.28 6888.52,3520 v1(6918,3520) 6918.56,3519.44 R30.2@7065.72,3519.44
  Top Layer w15: U19.5@6838.23,3409.69 U19.5@6842.54,3405.37 ; U13.5@7275.86,3357.34 U13.5@7280.81,3362.28 ; U13.5@7276.5,3363.15 7313.07,3363.15 7328.94,3347.28 C94.2@7332.87,3347.28 C94.2@7336.5,3343.66 ; U2.5@7543.23,4102.28 7549.09,4102.28 7555.91,4095.47 7555.91,4071.69 C34.1@7586.5,4041.1 ; C34.1@7589.25,4042.28 C34.1@7592.02,4039.52 ; U3.5@7634.09,3354.41 U3.5@7634.09,3356.59 ; U3.5@7634.09,3362.28 U3.5@7634.09,3356.59 ; U3.5@7638.41,3352.28 U3.5@7634.09,3356.59 ; C39.1@7697.05,3352.28 C39.1@7699.02,3354.25 ; D10.2@7807.19,3470.1 D10.2@7811.5,3474.41 ; D10.2@7811.5,3482.28 D10.2@7811.5,3474.41 ; 7823.68,3470.1 7815.81,3470.1 D10.2@7811.5,3474.41 ; D9.2@8051.5,3487.8 D9.2@8051.5,3495.67 ; C3.1@8224.25,3997.28 C3.1@8235.55,3985.98 8231.22,3981.65 U1.5@8231.22,3921.59
  Top Layer w20: v1(6604,4194) 6604,4129 v1(6717,4016) ; U19.5@6838.23,3409.69 6846.1,3409.69 6847.91,3407.87 6847.91,3391.09 6956.72,3282.28 7226.5,3282.28 7275.86,3331.65 U13.5@7275.86,3357.34 ; C94.2@7336.5,3343.66 7336.5,3327.28 7356.5,3307.28 7586.97,3307.28 U3.5@7634.09,3354.41 ; C34.1@7592.02,4039.52 7592.02,4002.98 7612.59,3982.41 ; 7614,3981 7882.72,3981 ; U3.5@7638.41,3352.28 C39.1@7697.05,3352.28 ; C39.1@7699.02,3354.25 7699.02,3374.8 7794.31,3470.1 D10.2@7807.19,3470.1 ; 7823.68,3470.1 7856.5,3437.28 8007.27,3437.28 8048.09,3478.11 8049.68,3478.11 8051.5,3479.92 D9.2@8051.5,3487.8 ; v1(7882.72,4163.5) 7882.72,3981 ; D9.2@8051.5,3495.67 8061.5,3505.67 8061.5,3979 ; C3.1@8231.22,3981.65 8230.57,3981 7882.72,3981
  Layer 3 w20: v1(6849,3713) 6849,3589 v1(6918,3520)
  Bottom Layer w10: U10.5@6601.8,4226 6602.9,4224.9 6602.9,4195.1 v1(6604,4194) ; U10.5@6606.8,4221 C125.2@6663,4221 ; C93.2@7852.72,4163.5 C93.2@7853.62,4164.4 ; C93.2@7863.62,4164.4 7864.53,4163.5 v1(7882.72,4163.5) 7906.81,4163.5 7907.72,4164.4 U12.3@7968.43,4164.4
  Bottom Layer w20: R55.2@6693.24,4016 v1(6717,4016) 6718,4016 6849,3885 v1(6849,3713)
5Vp: C30.1 C31.1 C35.1 C36.1 C88.1 C141.1 J8.3 J9.3 L4.2 U4.1 U5.1 U9.6 U18.10 U18.16 | length 687.7
  Top Layer w10: v1(1135,527) v1@1135.32,526.69 ; J9.3@1135.32,478.96 J9.3@1135.63,478.64 ; J8.3@1135.63,2224.92 J8.3@1136.82,2223.74 ; U9.6@1852.4,4007.87 1902.72,4007.87 L4.2@1917.87,3992.72 ; v1(1895,3954) 1895,3969.41 1915.59,3990 L4.2@1920.59,3990 ; C141.1@2089.09,3222.28 2094.09,3227.28 v4(2121.5,3227.28) U18.16@2167.17,3227.28 ; v1(2100.47,3652.28) 2120.47,3652.28 C36.1@2125.47,3647.28 ; U4.1@2117.91,3969.09 2124.72,3962.28 U4.1@2146.34,3962.28 ; U4.1@2120.37,3956.25 2144,3956.25 U4.1@2148.19,3960.44 ; v4(2125.47,3527.28) U18.10@2167.17,3527.28 ; C35.1@2125.47,3697.28 C36.1@2125.47,3647.28 ; C36.1@2130.47,3642.28 C36.1@2125.47,3647.28 ; U4.1@2158.25,3964 2159.11,3963.14 2190.14,3963.14 v4(2191,3964)
  Top Layer w20: J9.3@1135.32,478.96 v1@1135.32,526.69 ; J8.3@1136.82,2223.74 1140,2220.55 v1(1140,2182)
  Bottom Layer w10: v1(2044,3984) 2077,3984 C88.1@2084,3991 ; v1(2095,3945) 2096.85,3943.15 2096.85,3927.52 C31.1@2102.5,3921.87 2105.91,3925.28 C30.1@2154.09,3925.28 ; v1(2100.47,3652.28) 2103.09,3652.28 2106.28,3655.47 2139.53,3655.47 U5.1@2146.34,3662.28 ; C30.1@2155,3939.25 C30.1@2155.47,3938.78
5Vs: C32.1 C33.1 C37.1 C38.1 C82.1 C131.1 C140.2 C144.1 C149.1 J3.8 J5.48 J5.84 J5.98 J5.112 J6.8 J13.2 J15.2 L1.2 L7.2 R42.2 U4.8 U5.8 U16.6 U18.1 U18.7 U19.1 U19.3 U20.3 U20.4 | length 3388.8
  Top Layer w10: U18.7@2547.65,3523.91 U18.7@2551.02,3527.28 ; C140.2@2613.61,3526.8 2614.78,3527.97 C140.2@2615.47,3528.66 ; v1(5927,3636) 5927.08,3636.08 5927.08,3728.34 J5.112@5927.17,3728.43 ; J5.98@6147.64,3728.43 6147.82,3728.24 6147.82,3636.18 v1(6148,3636) ; v1(6368,3635) 6368.06,3635.06 J5.84@6368.11,3728.43 J5.84@6368.11,3728.43 ; U16.6@6471.81,3447.28 6471.81,3480.35 6489.33,3497.87 6494.09,3497.87 6514.69,3477.28 6549.09,3477.28 C131.1@6569.09,3457.28 v1(6569.09,3492.88) ; L7.2@6492.83,3507.87 L7.2@6492.83,3532.28 ; L7.2@6492.83,3537.28 6492.83,3554.41 6513.43,3575 v1(6530,3575) ; C131.1@6569.09,3442.28 6639.06,3442.28 6674.09,3407.24 6677.85,3411 v1(6697,3411) ; v1@6701.5,3409.69 U19.1@6729.96,3409.69 6736.77,3402.87 6755.91,3402.87 6766.5,3392.28 6766.5,3342.28 6759.09,3334.88 U19.3@6729.96,3334.88 U19.3@6729.96,3334.88 v1(6730,3315)
  Top Layer w15: U18.1@2528.17,3230 2537.97,3230 2545,3222.97 v1(2545,3205) ; v3(2531.5,3662.28) 2505.47,3688.31 2505.47,3952.81 2514.26,3961.59 2558.98,3961.59 C32.1@2558.98,4032.28 C38.1@2558.98,4082.97 ; U18.7@2551.02,3527.28 2551.71,3527.97 C140.2@2614.78,3527.97 ; C38.1@2557.17,4087.28 2558.6,4087.28 C38.1@2562.91,4082.97 ; C140.2@2615.76,3526.8 C140.2@2616.65,3525.91 ; v1(5333.11,1182.87) L1.2@5353.89,1182.87 ; J5.84@6368.11,3728.43 6368.11,3763.9 6399.21,3795 7023.78,3795 7058.68,3760.1 7058.68,3730.77 J5.48@7061.02,3728.43
  Top Layer w20: U18.1@2528.54,3225.47 2530.35,3227.28 U18.1@2545.47,3227.28 ; v1@2545.47,3205 U18.1@2545.47,3227.28 ; U18.1@2551.02,3227.28 U18.1@2545.47,3227.28 ; U4.8@2607.45,3962.28 2675.47,3962.28 J15.2@2770.47,4057.28 ; L1.2@5353.89,1182.87 5355.7,1184.68 L1.2@5355.7,1209.17
  Bottom Layer w10: v3(2531.5,3662.28) U5.8@2575.47,3662.28 C37.1@2681.48,3662.28 ; C37.1@2676.77,3676.77 2685.63,3685.63 2729.96,3685.63 C33.1@2736.77,3692.44 C33.1@2736.77,3693.54 ; C82.1@5201.61,1227.87 C82.1@5206.61,1232.87 C82.1@5207.36,1233.62 ; R42.2@5207.36,1297.12 R42.2@5208.11,1297.87
  Bottom Layer w15: C82.1@5201.61,1227.87 5201.61,1182.87 ; C82.1@5207.36,1233.62 R42.2@5207.36,1297.12 ; J13.2@5261.61,1059.33 5201.61,1119.33 5201.61,1182.87 ; v1(5333.11,1182.87) 5201.61,1182.87 ; v1(6697,3411) 6697.74,3411.74 6730.76,3411.74 U20.4@6731.5,3412.48 U20.3@6839.76,3412.48 6892.87,3412.48 C149.1@6902.68,3422.28
  Bottom Layer w20: J6.8@2688.39,584.24 J6.8@2690,585.85
  other v1: 2593.82,3527.97
6V: C71.1 C72.1 C80.1 D12.1 U7.4 U7.5 | length 327.9
  Top Layer w10: v1(5443.11,1511.57) 5443.11,1477.83 C71.1@5456.61,1464.33
  Bottom Layer w15: D12.1@5421.61,1579.33 D12.1@5424.6,1576.34 5443.11,1557.83 v1(5443.11,1511.57) 5443.11,1487.87 C72.1@5438.11,1482.87 C80.1@5438.11,1417.87 5444.92,1411.06 5444.92,1364.58 5449.23,1360.27 U7.4@5452.24,1360.27 U7.5@5452.24,1322.87
12Vp: 12Vp.1 C70.1 C84.2 C85.2 C86.1 D8.1 D11.2 D13.1 J7.5 J8.1 J9.1 J14.1 U9.2 U9.3 | length 1604.5
  Top Layer w10: J9.1@1185.63,478.64 J9.1@1185.82,478.83 ; J8.1@1185.63,2224.92 J8.1@1186.82,2226.11 ; v1@1185.82,525.82 v1(1186,526) ; C85.2@1610,3937.09 1634.41,3937.09 1655,3916.5 v1(1655,3900) ; v1(1700,3900) 1700,3917.32 C84.2@1727.68,3945 ; C84.2@1745,3937.09 1735.59,3937.09 C84.2@1727.68,3945 ; U9.3@1777.6,4007.87 1777.6,4027.56 1717.44,4027.56 C86.1@1715,4030 ; 12Vp.1@1915,4300 12Vp.1@1917.74,4297.26 ; J7.5@1917.74,4165.02 J7.5@1920.47,4162.28 1909.28,4162.28 1847,4100 1750.86,4100 1735,4084.14 1735,4050 C86.1@1715,4030 ; D8.1@4279.92,1428.97 D8.1@4289.56,1419.33 ; C86.1@1715,4030 1715,3957.68 C84.2@1727.68,3945
  Top Layer w15: J7.5@1917.74,4165.02 12Vp.1@1917.74,4297.26
  Top Layer w20: J9.1@1185.82,478.83 v1@1185.82,525.82 ; J8.1@1186.82,2226.11 1189,2228.29 v1(1189,2268) ; D13.1@4172.77,1414.33 D8.1@4284.56,1414.33 ; D8.1@4279.92,1428.97 D11.2@4279.92,1524.33 ; D8.1@4289.56,1419.33 D8.1@4284.56,1414.33 ; J14.1@4401.61,957.28 4300,1058.89 4300,1202.83 4278.5,1224.33 C70.1@4255.04,1224.33 4272,1241.29 4272,1401.76 D8.1@4284.56,1414.33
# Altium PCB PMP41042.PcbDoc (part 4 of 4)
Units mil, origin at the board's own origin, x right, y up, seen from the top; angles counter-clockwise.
Board outline 9847.6 x 4445 mil, 6 copper layers (Top Layer, Layer 1, Layer 2, Layer 3, Layer 4, Bottom Layer), stack 32.112 mil thick; 329 components, 129 nets, 1246 pads, 863 vias.
Unrouted connection lines stored in the file: 6.

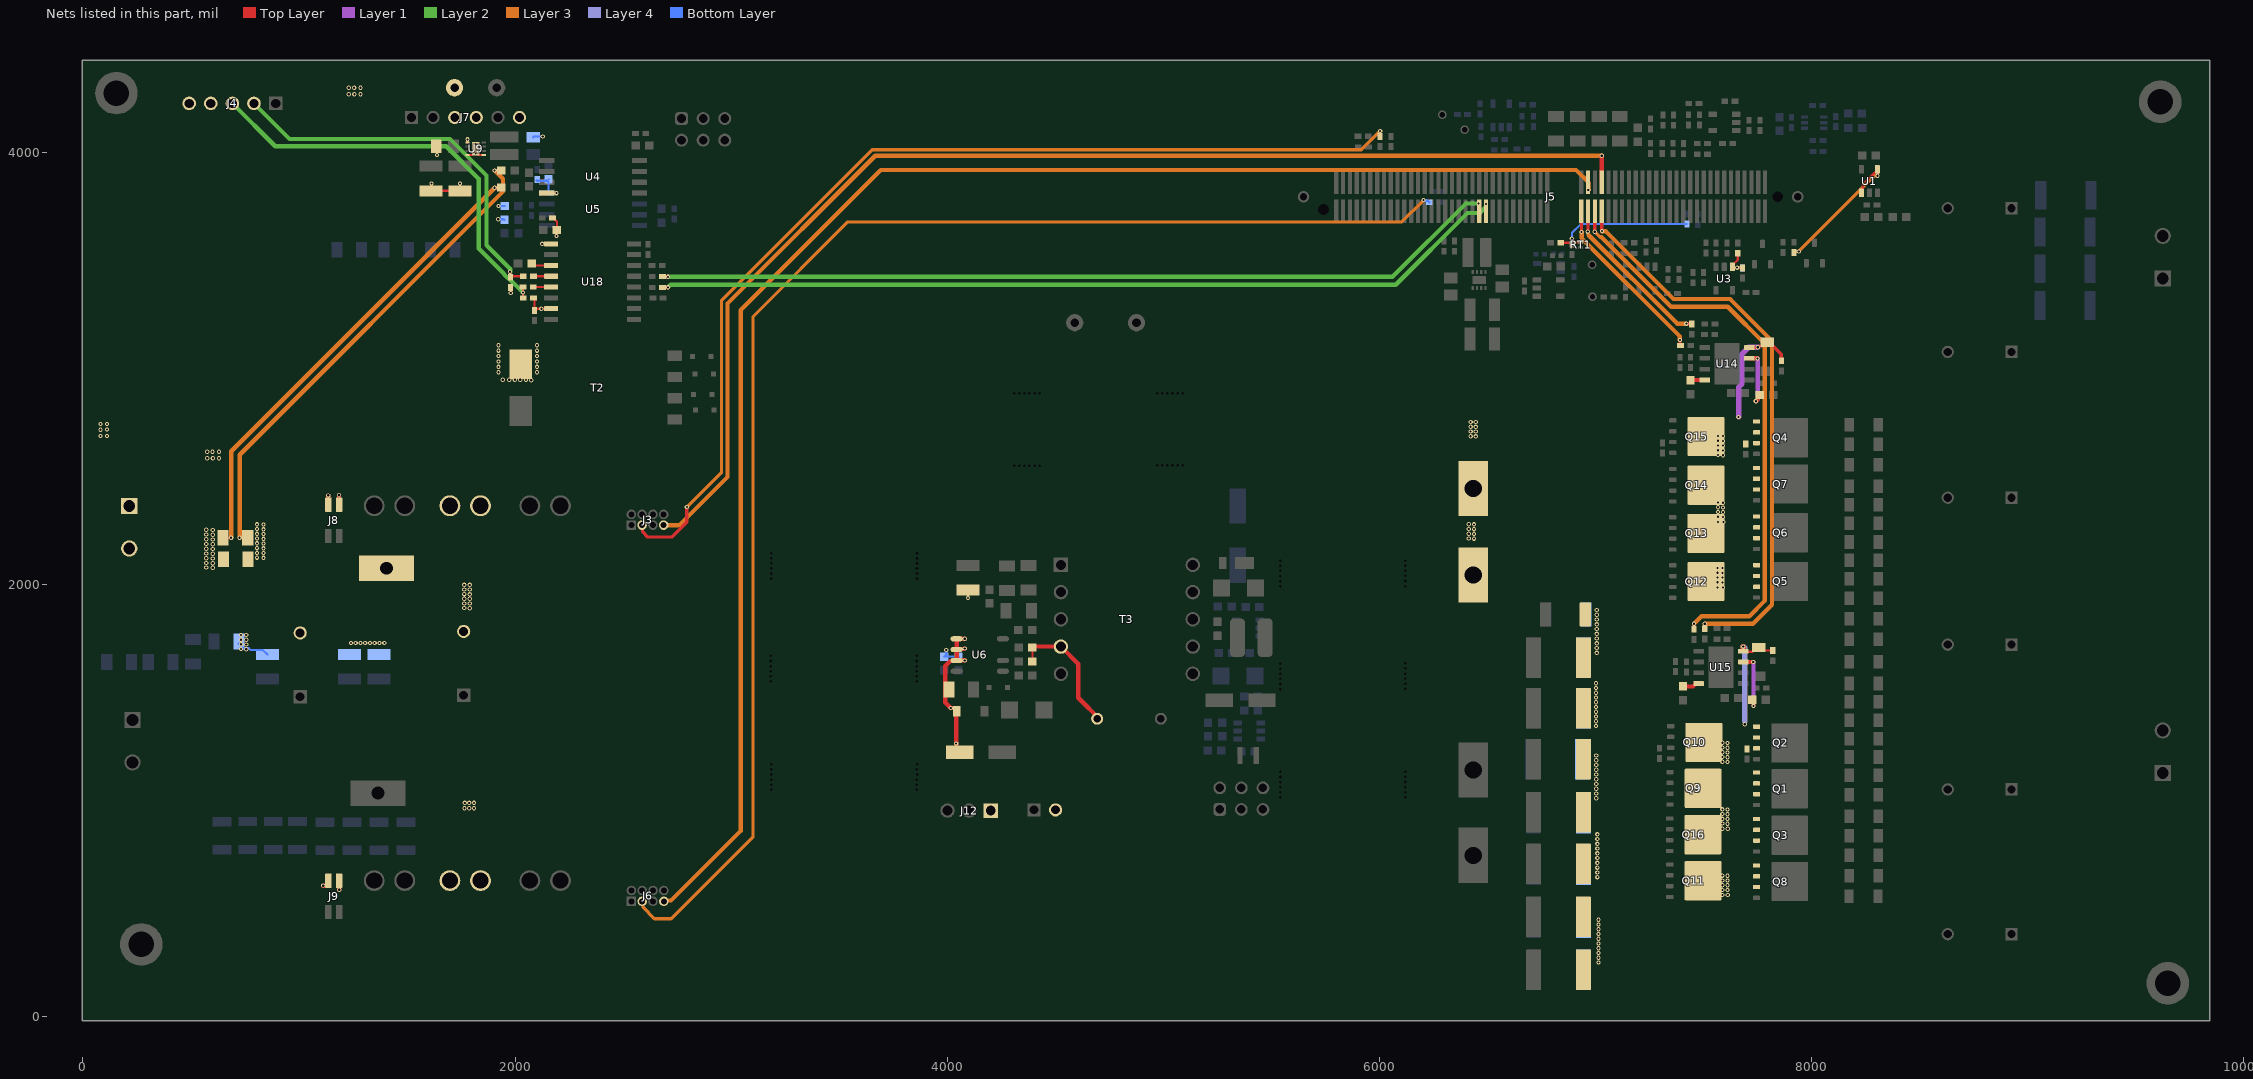
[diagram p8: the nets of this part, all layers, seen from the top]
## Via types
v1: diameter 19.68, hole 10, Top Layer to Bottom Layer, tented both sides, 821 vias
v2: diameter 19.68, hole 7.87, Top Layer to Bottom Layer, 12 vias
v3: diameter 19.68, hole 12, Top Layer to Bottom Layer, tented both sides, 11 vias
v4: diameter 20, hole 10, Top Layer to Bottom Layer, tented both sides, 11 vias
v5: diameter 19.68, hole 7.87, Top Layer to Bottom Layer, tented both sides, 8 vias

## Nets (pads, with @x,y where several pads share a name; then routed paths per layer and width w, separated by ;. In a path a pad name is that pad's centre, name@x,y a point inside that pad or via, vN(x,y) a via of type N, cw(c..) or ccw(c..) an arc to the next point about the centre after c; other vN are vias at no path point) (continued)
NetR104_1: R104.1 U18.13 | length 93.6
  Top Layer w10: R104.1@2073.9,3377.44 2167.01,3377.44 U18.13@2167.17,3377.28 ; R104.1@2083.74,3377.6 R104.1@2083.9,3377.44
NetR106_1: R106.1 U18.12 | length 92.2
  Top Layer w10: R106.1@2075.28,3427.44 2167.01,3427.44 U18.12@2167.17,3427.28 ; R106.1@2085.12,3427.6 R106.1@2085.28,3427.44
NetT2_1: pad.2@1405,2075.63 T2.1
  other v1: 2075,2946 2050,2947 1943,2948 1973,2948 1999,2948 2024,2948 1923,2983 2101,2983 1923,3008 2101,3008 1923,3033 2101,3033 1923,3058 2101,3058 1923,3083 2101,3083 1923,3108 2101,3108
PFC_Fault: R74.1 U18.11 | length 94.8
  Top Layer w10: R74.1@2076.5,3487.28 2086.5,3477.28 U18.11@2167.17,3477.28
PGND: C8.2 C11.2 C12.2 C13.2 C30.2 C31.2 C35.2 C36.2 C65.2 C67.2 C70.2 C73.2 C74.2 C75.2 C84.1 C85.1 C86.2 C88.2 C101.2 C141.2 C147.2 C148.2 D13.2 J4.4 J4.5 J7.3 J7.4 J7.6 J8.2 J8.4 J9.2 J9.4 J12.1 J14.2 PGND1.1 PGND2.1 PGND.1 R7.1 R8.2 R9.2 R18.1 R27.1 R28.1 R40.1 R41.1 T3.4 U4.4 U5.4 U6.1 U6.2 U6.3 U9.1 U9.4 U9.5 U9.9@1817.6,4017.53 U18.9 U18.15 | length 5107.5
  Top Layer w10: v1(725.16,2217.28) R8.2@762.56,2217.28 ; v3(1135,2413) v3@1135.32,2412.68 ; J8.4@1135.32,2370.31 J8.4@1135.63,2370 ; v3(1185,2415) v3@1185.32,2414.68 ; J8.2@1185.32,2370.31 J8.2@1185.63,2370 ; J9.2@1185.63,623.72 J9.2@1185.82,623.54 ; v3@1185.82,588.18 v3(1186,588) ; v1(1613,3857) 1613,3825.91 C85.1@1610,3822.91 1740,3822.91 C84.1@1745,3822.91 v1(1745,3857) ; C86.2@1635,4030 1639,4026 v1(1639,3989) ; U9.4@1777.6,3988.19 1777.68,3988.27 1799.33,3988.27 U9.9@1811.06,4000 ; v1@1780,4055.16 1780,4049.65 1778.72,4048.37 1778.72,4047.24 1778.72,4059.72 v1(1780,4061) ; U9.9@1815,4031.5 1815,4017.72 1815,4003.94 1830.67,3988.27 1852.32,3988.27 U9.5@1852.4,3988.19 ; C147.2@1979.68,3375.32 1979.84,3375.16 1979.84,3350.16 v4(1980,3350) ; C148.2@2085.28,3327.28 C148.2@2089.09,3327.28 ; C141.2@2089.09,3269.53 C141.2@2089.09,3270.47 ; C148.2@2096.02,3320.47 2089.21,3327.28 C148.2@2089.09,3327.28 ; U4.4@2120.37,3806.25 2144,3806.25 2149.89,3812.14 2191.86,3812.14 v4(2192,3812) ; v4(2125.47,3577.28) U18.9@2167.17,3577.28 ; U18.15@2167.17,3277.28 v4(2121.5,3277.28) 2095.91,3277.28 C141.2@2089.09,3270.47 ; C35.2@2172.72,3697.28 2176.65,3697.28 2193.46,3680.47 C36.2@2193.46,3642.28 2192,3640.82 v4(2192,3614) ; v1(4096.61,1938.89) C67.2@4096.61,1974.33 ; J12.1@4201.61,954.33 J12.1@4206.77,949.17 ; R40.1@4394.6,1644.33 C75.2@4394.6,1709.33 ; C75.2@4406.45,1708.03 C75.2@4411.77,1713.34 ; C141.2@2089.09,3270.47 C148.2@2089.09,3327.28
  Top Layer w15: v4(1905.47,3917.28) R18.1@1935,3917.28
  Top Layer w20: v3(1112,607) 1131.06,607 1131.91,607.85 J9.4@1131.91,620 ; J8.4@1135.32,2370.31 v3@1135.32,2412.68 ; J8.2@1185.32,2370.31 v3@1185.32,2414.68 ; v3@1185.82,588.18 J9.2@1185.82,623.54 ; C70.2@4058.19,1224.33 4041.61,1240.9 v1(4041.61,1264.33) 4041.61,1414.09 4043.83,1416.32 4030.82,1429.33 v1(4016.61,1429.33) 3991.22,1454.72 3991.22,1514.33 3991.22,1623.47 3997.07,1629.33 4014.47,1646.72 4041.13,1646.72 U6.3@4043.74,1649.33 ; v1(4081.61,1649.33) U6.3@4043.74,1649.33 ; v1(4081.61,1704.33) 4078.99,1704.33 4076.6,1701.93 4046.34,1701.93 U6.2@4043.74,1699.33 ; v1(4081.61,1749.33) U6.1@4043.74,1749.33 U6.2@4043.74,1699.33 ; C75.2@4411.77,1713.34 T3.4@4506.49,1713.34 ; T3.4@4526.49,1713.34 4606.61,1633.23 4606.61,1476.53 C65.2@4710.01,1373.13 ; U6.3@4043.74,1649.33 U6.2@4043.74,1699.33
  Layer 3 w20: v1@725.16,2217.67 725.16,2601.16 1944,3820 1944,3878.76 v4(1905.47,3917.28)
  Bottom Layer w10: R7.1@721.18,1726.46 741.77,1705.87 767.91,1705.87 776.73,1697.05 833.5,1697.05 C13.2@854.09,1676.46 ; v1(1921.93,3690.98) v1(1921.93,3690.98) 1948.27,3690.98 R27.1@1950.47,3688.78 ; v4(1922.95,3752.28) R28.1@1952.48,3752.28 ; C88.2@2084,4071 2087,4074 v1(2128,4074) ; C31.2@2099.09,3869.09 2148.78,3869.09 C30.2@2155.47,3875.79 ; C30.2@2154.09,3862.28 2154.09,3819.09 2147.28,3812.28 U5.4@2146.34,3812.28 2146.48,3812.14 2191.86,3812.14 v4(2192,3812) ; v1(3996,1697) 3996,1676.71 C74.2@3986.61,1667.32 R41.1@4051.61,1667.32 4051.61,1666.34 4065.31,1652.63 4066.3,1652.63 4067.75,1651.18 4079.76,1651.18 v1(4081.61,1649.33)
  other v1: 1766,965 1788,965 1810,965 1767,990 1788,990 1810,990 756.02,1700.85 731.02,1701.85 756.02,1722.85 731.02,1723.85 1240,1730 1262,1730 1284,1730 1306,1730 1328,1730 1350,1730 1372,1730 1395,1730 731.02,1744.85 756.02,1744.85 731.02,1766.85 756.02,1766.85 1790,1891 1765,1892 1765,1913 1790,1913 1765,1935 1790,1935 1790,1955 1765,1956 1765,1977 1790,1977 1765,1999 1790,1999 835,2124 805,2125 835,2146 805,2147 835,2168 805,2169 835,2190 805,2191 835,2212 805,2213 835,2234 805,2235 835,2256 805,2257 835,2278 805,2279 575,2585 601.07,2584.89 630,2585 575,2615 600,2615 630,2615 81.61,2688.35 111.61,2688.35 81.5,2717.28 111.61,2718.35 81.61,2743.35 111.61,2743.35 1230,4270 1256.07,4269.89 1285,4270 1230,4300 1255,4300 1285,4300
  other v2: 1817.6,3995.87 1817.6,4039.18
RTN: J2.1 J2.2 R8.1 R9.1 R24.1 | length 2192.1
  Top Layer w10: R8.1@648.39,2217.28 v1(685.79,2217.28)
  Top Layer w15: v4(1905.47,3837.28) R24.1@1935,3837.28
  Layer 3 w20: v1(685.79,2217.28) 685.79,2617.6 v4(1905.47,3837.28)
  other v1: 600.47,2078.28 570.47,2079.28 600.47,2099.28 570.47,2100.28 600.47,2121.28 570.47,2122.28 600.47,2143.28 570.47,2144.28 600.47,2165.28 570.47,2166.28 600.47,2187.28 570.47,2188.28 600.47,2209.28 570.47,2210.28 600.47,2231.28 570.47,2232.28 600.47,2253.28 570.47,2254.28
SCI_RX0: J5.76 R103.1 | length 4013.5
  Top Layer w10: J5.76@6492.8,3729.72 J5.76@6494.09,3728.43
  Top Layer w15: R103.1@2682.52,3376.06 v1(2708.11,3376.06) ; J5.76@6492.8,3729.72 6494.05,3730.98 6494.05,3761.95 v1(6494,3762)
  Layer 2 w20: v1(2708.11,3376.06) 2720.05,3388 6076,3388 6408,3720 6464.84,3720 6494,3749.16 v1(6494,3762)
SCI_RX0_PFC: C148.1 J4.3 R104.2 | length 1958.8
  Top Layer w10: J4.3@691.5,4218.5 J4.3@691.5,4227.28 ; v1@2036.5,3350.97 R104.2@2036.5,3377.6 ; v1(2037,3352) 2037,3328.32 C148.1@2038.03,3327.28
  Layer 2 w20: J4.3@691.5,4227.28 889.78,4029 1681,4029 1832,3878 1832,3556 1949,3439 1949,3436.4 1965.4,3420 1968,3420 2036,3352 v1(2037,3352)
SCI_TX0: J5.78 R105.1 | length 3955.7
  Top Layer w10: v1(6459.98,3764.3) J5.78@6461.29,3762.99 ; J5.78@6461.29,3729.74 J5.78@6462.6,3728.43
  Top Layer w15: R105.1@2682.52,3426.06 2683.22,3425.36 2707.41,3425.36 v1(2708.11,3424.66) ; J5.78@6461.29,3729.74 J5.78@6461.29,3762.99
  Layer 2 w20: v1(2708.11,3424.66) 6061.66,3424.66 6401.3,3764.3 v1(6459.98,3764.3)
SCI_TX0_PFC: C147.1 J4.2 R106.2 | length 1792.5
  Top Layer w10: v1(1977,3448) 1978.34,3446.66 1978.34,3423.9 C147.1@1979.68,3422.56 1984.72,3427.6 R106.2@2037.87,3427.6
  Layer 2 w20: J4.2@791.5,4227.28 955.78,4063 1699,4063 1868,3894 1868,3571 1977,3462 v1(1977,3448)
SEC_SW1: C105.2 C106.2 pad.2@6435,2045 pad.2@6435,2445 Q4.1 Q4.2 Q4.3 Q5.1 Q5.2 Q5.3 Q6.1 Q6.2 Q6.3 Q7.1 Q7.2 Q7.3 Q12.5 Q12.6 Q12.7 Q12.8 Q12.9@7512.56,2014.41 Q13.5 Q13.6 Q13.7 Q13.8 Q13.9@7511.61,2237.28 Q14.5 Q14.6 Q14.7 Q14.8 Q14.9@7512.56,2460.16 Q15.5 Q15.6 Q15.7 Q15.8 Q15.9@7512.56,2685.16 R38.1 U14.4 | length 583.3
  Top Layer w15: U14.4@7713.19,3097.28 U14.4@7720.67,3097.28 ; U14.4@7731.61,3098 7751,3098 v1(7752,3099) 7754.62,3099 7760.11,3104.49 7770,3104.49 7786.65,3121.14 7806.34,3121.14 7860.28,3067.2 7860.28,3037.68 C106.2@7861.5,3036.46
  Layer 1 w25: v1(7663,2776) 7663,2913.6 7679.12,2929.72 7679.12,3067.28 7710.83,3099 v1(7752,3099)
  other v1: 7565.47,1987.28 7590.47,1987.28 7589,2010.61 7565.47,2011.26 7589,2032.62 7565.47,2033.27 7589,2054.63 7565.47,2055.28 7589,2076.63 7565.47,2077.28 6414.5,2213.57 6438.03,2212.92 6414.5,2235.58 6438.03,2234.93 6414.5,2257.59 6438.03,2256.94 6414.5,2279.59 6438.03,2278.94 7567.97,2289.94 7592.97,2289.94 7591.5,2313.27 7567.97,2313.92 7591.5,2335.28 7567.97,2335.93 7591.5,2357.28 7567.97,2357.93 7591.5,2379.29 7567.97,2379.94 7591.5,2599.25 7567.97,2599.9 7591.5,2621.26 7567.97,2621.91 7591.5,2643.27 7567.97,2643.92 7591.5,2665.28 7567.97,2665.93 6446.5,2686.26 6422.97,2686.91 7591.5,2687.28 7567.97,2687.93 6446.5,2708.27 6422.97,2708.92 6446.5,2730.28 6422.97,2730.93 6446.5,2752.28 6422.97,2752.93
SEC_SW2: C2.2 C4.2 C6.2 C7.2 C10.2 C14.2 C16.2 C17.2 C19.2 C20.2 C21.2 C22.2 C23.2 C24.2 C27.2 C28.2 C120.2 C121.2 Q1.1 Q1.2 Q1.3 Q2.1 Q2.2 Q2.3 Q3.1 Q3.2 Q3.3 Q8.1 Q8.2 Q8.3 Q9.5 Q9.6 Q9.7 Q9.8 Q9.9@7499.09,1057.28 Q10.5 Q10.6 Q10.7 Q10.8 Q10.9@7502.56,1270.16 Q11.5 Q11.6 Q11.7 Q11.8 Q11.9@7498.7,629.41 Q16.5 Q16.6 Q16.7 Q16.8 Q16.9@7497.64,842.28 R39.1 U15.4 | length 518.4
  Top Layer w10: U15.4@7685,1695.35 7690.67,1689.69 7727.13,1689.69 7746.65,1709.21 C120.2@7756.5,1709.21 7771.18,1694.53 C121.2@7821.5,1694.53
  Top Layer w25: U15.4@7685,1695.35 v1(7685,1713)
  Layer 4 w25: v1(7685,1713) 7691,1707 7691,1367.78
  other v1: 7014.48,251.13 7014.48,273.14 7014.48,295.15 7014.48,317.16 7014.48,339.16 7014.48,361.17 7014.48,383.18 7014.48,405.19 7014.48,427.2 7014.48,449.2 7587.97,562.93 7612.97,562.93 7611.5,586.26 7587.97,586.91 7611.5,608.27 7587.97,608.92 7611.5,630.28 7587.97,630.93 7009.48,646.13 7611.5,652.28 7587.97,652.93 7009.48,668.14 7009.48,690.15 7009.48,712.16 7009.48,734.16 7009.48,756.17 7009.48,778.18 7009.48,800.19 7009.48,822.2 7009.48,844.2 7587.97,869.94 7612.97,869.94 7611.5,893.27 7587.97,893.92 7611.5,915.28 7587.97,915.93 7611.5,937.28 7587.97,937.93 7611.5,959.29 7587.97,959.94 7004.48,1011.13 7004.48,1033.14 7004.48,1055.15 7004.48,1077.16 7004.48,1099.16 7004.48,1121.17 7004.48,1143.18 7004.48,1165.19 7611.5,1179.25 7587.97,1179.9 7004.48,1187.2 7611.5,1201.26 7587.97,1201.91 7004.48,1209.2 7611.5,1223.27 7587.97,1223.92 7611.5,1245.28 7587.97,1245.93 7611.5,1267.28 7587.97,1267.93 7003.71,1345.77 7692,1354 7003.71,1367.78 7003.71,1389.79 7003.71,1411.8 7003.71,1433.81 7003.71,1455.81 7003.71,1477.82 7003.71,1499.83 7003.71,1521.84 7003.71,1543.85 7006.5,1684.21 7006.5,1706.22 7006.5,1728.23 7006.5,1750.24 7006.5,1772.24 7006.5,1794.25 7006.5,1816.26 7006.5,1838.27 7006.5,1860.28 7006.5,1882.28
SR_HA: R36.1 U14.3 | length 275.5
  Top Layer w10: R36.1@7752,2869.28 R36.1@7760,2877.28
  Top Layer w20: U14.3@7713.19,3047.28 v1(7750.66,3047.28) ; v1(7743,2849) 7750.31,2856.31 7750.31,2868.58 7751.02,2869.28 R36.1@7752,2869.28
  Layer 1 w20: v1(7743,2849) 7751.5,2857.5 7751.5,3046.45 v1(7750.66,3047.28)
SR_HB: R37.2 U15.3 | length 277.7
  Top Layer w10: U15.3@7687.44,1642.28 U15.3@7687.58,1642.14 ; R37.2@7726.5,1467.28 R37.2@7732,1461.78 ; v1@7730.86,1642.14 v1(7731,1642)
  Top Layer w20: U15.3@7687.58,1642.14 v1@7730.86,1642.14 ; v1(7732,1439) R37.2@7732,1461.78
  Layer 1 w10: v1(7731,1642) v1@7732,1641
  Layer 1 w20: v1(7732,1439) v1@7732,1641
SR_LA: R47.1 U14.8 | length 65.8
  Top Layer w10: R47.1@7441.5,2945.28 R47.1@7443.5,2947.28
  Top Layer w20: R47.1@7443.5,2947.28 U14.8@7506.5,2947.28
SR_LB: R48.2 U15.8 | length 77.8
  Top Layer w20: R48.2@7406.5,1528.78 7451.83,1528.78 7463.54,1540.5 7463.54,1541.46 7464.37,1542.28 U15.8@7478.15,1542.28
SR_PWM_HA: J5.54 R77.1 | length 760.7
  Top Layer w10: v1(6965.34,3633.89) v1@6965.94,3634.49 ; J5.54@6965.94,3727.83 J5.54@6966.54,3728.43 ; R77.1@7444.33,3208.07 R77.1@7446.5,3205.91
  Top Layer w15: v1@6965.94,3634.49 J5.54@6965.94,3727.83 ; v1(7421.5,3208.07) R77.1@7444.33,3208.07
  Layer 3 w15: v1(6965.34,3633.89) 6966.23,3633 6966.23,3620.65 6969.65,3617.24
  Layer 3 w20: 6969.65,3617.24 7378.82,3208.07 v1(7421.5,3208.07)
SR_PWM_HB: J5.50 R90.1 | length 2682.7
  Top Layer w10: J5.50@7029.53,3728.43 J5.50@7030.05,3727.91 ; v1@7030.05,3636.88 v1(7030.57,3636.36)
  Top Layer w15: v1@7030.05,3636.88 J5.50@7030.05,3727.91 ; R90.1@7506.5,1795.91 v1(7506.5,1819)
  Layer 3 w20: v1(7030.57,3636.36) 7047.64,3636.36 7362.06,3321.94 7624.06,3321.94 7818,3128 7818,1906.72 7730.28,1819 v1(7506.5,1819)
SR_PWM_LA: J5.56 R78.1 | length 811.4
  Top Layer w10: J5.56@6935.04,3728.43 J5.56@6935.77,3727.7 ; v1@6935.77,3633.01 v1(6936.5,3632.28) ; R78.1@7391.5,3110.04 R78.1@7394.25,3107.28
  Top Layer w15: v1@6935.77,3633.01 J5.56@6935.77,3727.7 ; R78.1@7391.5,3110.04 v1(7391.5,3132.28)
  Layer 3 w20: v1(6936.5,3632.28) 6936.5,3603.5 7391.5,3148.5 v1(7391.5,3132.28)
SR_PWM_LB: J5.52 R91.1 | length 2684.1
  Top Layer w10: v1(6997.65,3633.44) v1@6997.84,3633.63 ; J5.52@6997.84,3728.23 J5.52@6998.03,3728.43
  Top Layer w15: v1@6997.84,3633.63 J5.52@6997.84,3728.23 ; R91.1@7456.5,1793.66 v1(7456.5,1819.25)
  Layer 3 w15: v1(6997.65,3633.44) 6997.65,3633.21 7022.51,3608.36 7028.64,3608.36
  Layer 3 w20: 7028.64,3608.36 7351,3286 7613,3286 7785,3114 7785,1926 7713,1854 7491.24,1854 v1(7456.5,1819.25)
TMP_SEC: C97.1 R67.2 R76.2 RT1.2 | length 685.1
  Top Layer w10: C97.1@6840.12,3582.28 6887.13,3582.28 R67.2@6889.92,3585.08 ; v1(6891.5,3601.5) 6891.5,3586.65 R67.2@6889.92,3585.08 ; RT1.2@6931.5,3585.08 R67.2@6889.92,3585.08
  Bottom Layer w10: v1(6891.5,3601.5) 6891.5,3627.28 6932.87,3668.66 R76.2@7424.09,3668.66
Top_FET_FAULT1: J3.3 R101.1 | length 4768.5
  Top Layer w10: R101.1@6004.09,4074.53 v1(6004.09,4100.12)
  Top Layer w15: J3.3@2587.99,2275.39 2590.15,2273.23 2590.15,2243.85 2614,2220 2726,2220 2795,2289 v1(2795,2359)
  Layer 3 w15: v1(2795,2359) 2956,2520 2956,3317 3652.5,4013.5 5917.48,4013.5 v1(6004.09,4100.12)
Top_FET_FAULT2: J6.3 R98.1 | length 6483.2
  Layer 3 w15: J6.3@2588.39,535.24 2592.57,531.05 2592.57,506.43 2645,454 2722,454 3101.5,833.5 3101.5,3241.03 3539.47,3679 6104,3679 v1(6205,3780)
  Bottom Layer w10: v1(6205,3780) 6207.62,3780 6210.81,3776.81 6224.57,3776.81 R98.1@6231.38,3770
Top_FET_PWM1: J3.7 J5.49 | length 5643.4
  Top Layer w10: J5.49@7029.53,3862.28 J5.49@7029.76,3862.52
  Top Layer w20: J5.49@7029.76,3862.52 7029.76,3984.76 v1(7030,3985)
  Layer 3 w20: J3.7@2687.99,2275.39 2760.39,2275.39 2983,2498 2983,3301 3667,3985 v1(7030,3985)
Top_FET_PWM2: J5.53 J6.7 | length 7186.6
  Top Layer w20: J5.53@6966.54,3862.28 6966.69,3862.13 6966.69,3827.31 v1(6967,3827)
  Layer 3 w20: J6.7@2688.39,535.24 2691.15,538 2722,538 3044,860 3044,3270 3693,3919 6911,3919 6967,3863 v1(6967,3827)
VSNS_PRI: C29.2 R16.2 R81.2 U3.1 | length 148.7
  Top Layer w10: R81.2@7659.09,3533.66 7659.09,3502.91 7641.42,3485.24 7640.91,3485.24 7634.09,3478.43 U3.1@7634.09,3470.55 7637.36,3467.28 v1(7656.5,3467.28) 7680.12,3467.28 C29.2@7681.5,3465.91
  Bottom Layer w10: v1(7656.5,3467.28) 7680.12,3467.28 R16.2@7681.5,3465.91
VSNS_SEC: R83.2 U1.1 U1.4 | length 707.1
  Top Layer w10: R83.2@7919.09,3537.28 7924.09,3542.28 v1(7941.5,3542.28) ; U1.1@8231.22,3813.33 8237.65,3819.75 8237.65,3852.19 8292.36,3906.91 8299.21,3906.91 8306.02,3913.72 U1.4@8306.02,3921.59 8306.26,3921.36 8306.26,3892.52 v1(8306.5,3892.28)
  Layer 3 w15: v1(7941.5,3542.28) 8291.43,3892.22 v1@8306.43,3892.22
pads on no net: J5.1 J5.2 J5.3 J5.4 J5.5 J5.6 J5.8 J5.9 J5.11 J5.12 J5.13 J5.15 J5.16 J5.17 J5.20 J5.26 J5.28 J5.29 J5.32 J5.33 J5.36 J5.37 J5.39 J5.40 J5.41 J5.42 J5.43 J5.44 J5.45 J5.57 J5.58 J5.59 J5.60 J5.61 J5.62 J5.63 J5.64 J5.66 J5.67 J5.68 J5.69 J5.70 J5.71 J5.72 J5.73 J5.75 J5.77 J5.79 J5.80 J5.81 J5.82 J5.85 J5.87 J5.89 J5.90 J5.91 J5.92 J5.93 J5.94 J5.95 J5.96 J5.99 J5.100 J5.101 J5.102 J5.104 J5.106 J5.107 J5.108 J5.109 J5.110 J5.113 J5.114 J5.115 J5.116 J5.117 J5.118 J5.119 J5.120 J5.181 J5.182 J5.185 J5.186 J7.2 J12.2 Q1.9@7850.43,997.28 Q1.9@7850.43,1055.16 Q1.9@7850.43,1113.03 Q1.9@7916.57,997.28 Q1.9@7916.57,1055.16 Q1.9@7916.57,1113.03 Q2.9@7850.43,1209.41 Q2.9@7850.43,1267.28 Q2.9@7850.43,1325.16 Q2.9@7916.57,1209.41 Q2.9@7916.57,1267.28 Q2.9@7916.57,1325.16 Q3.9@7850.43,782.28 Q3.9@7850.43,840.16 Q3.9@7850.43,898.03 Q3.9@7916.57,782.28 Q3.9@7916.57,840.16 Q3.9@7916.57,898.03 Q4.9@7850.43,2622.28 Q4.9@7850.43,2680.16 Q4.9@7850.43,2738.03 Q4.9@7916.57,2622.28 Q4.9@7916.57,2680.16 Q4.9@7916.57,2738.03 Q5.9@7850.43,1957.28 Q5.9@7850.43,2015.16 Q5.9@7850.43,2073.03 Q5.9@7916.57,1957.28 Q5.9@7916.57,2015.16 Q5.9@7916.57,2073.03 Q6.9@7850.43,2182.28 Q6.9@7850.43,2240.16 Q6.9@7850.43,2298.03 Q6.9@7916.57,2182.28 Q6.9@7916.57,2240.16 Q6.9@7916.57,2298.03 Q7.9@7850.43,2407.28 Q7.9@7850.43,2465.16 Q7.9@7850.43,2523.03 Q7.9@7916.57,2407.28 Q7.9@7916.57,2465.16 Q7.9@7916.57,2523.03 Q8.9@7850.43,567.28 Q8.9@7850.43,625.16 Q8.9@7850.43,683.03 Q8.9@7916.57,567.28 Q8.9@7916.57,625.16 Q8.9@7916.57,683.03 Q9.9@7449.49,999.41 Q9.9@7449.49,1057.28 Q9.9@7449.49,1115.16 Q9.9@7515.63,999.41 Q9.9@7515.63,1057.28 Q9.9@7515.63,1115.16 Q10.9@7452.95,1212.28 Q10.9@7452.95,1270.16 Q10.9@7452.95,1328.03 Q10.9@7519.09,1212.28 Q10.9@7519.09,1270.16 Q10.9@7519.09,1328.03 Q11.9@7449.09,571.54 Q11.9@7449.09,629.41 Q11.9@7449.09,687.28 Q11.9@7515.24,571.54 Q11.9@7515.24,629.41 Q11.9@7515.24,687.28 Q12.9@7462.95,1956.54 Q12.9@7462.95,2014.41 Q12.9@7462.95,2072.28 Q12.9@7529.09,1956.54 Q12.9@7529.09,2014.41 Q12.9@7529.09,2072.28 Q13.9@7462.01,2179.41 Q13.9@7462.01,2237.28 Q13.9@7462.01,2295.16 Q13.9@7528.15,2179.41 Q13.9@7528.15,2237.28 Q13.9@7528.15,2295.16 Q14.9@7462.95,2402.28 Q14.9@7462.95,2460.16 Q14.9@7462.95,2518.03 Q14.9@7529.09,2402.28 Q14.9@7529.09,2460.16 Q14.9@7529.09,2518.03 Q15.9@7462.95,2627.28 Q15.9@7462.95,2685.16 Q15.9@7462.95,2743.03 Q15.9@7529.09,2627.28 Q15.9@7529.09,2685.16 Q15.9@7529.09,2743.03 Q16.9@7448.03,784.41 Q16.9@7448.03,842.28 Q16.9@7448.03,900.16 Q16.9@7514.17,784.41 Q16.9@7514.17,842.28 Q16.9@7514.17,900.16 RT1.1S RT1.2S T2.3 T2.4 T3.2 T3.6 U9.8 U9.9@1817.6,3999.81 U9.9@1817.6,4035.24 U14.9@7609.84,3022.28 U15.9@7581.5,1617.28 U16.8 U16.9@6444.25,3409.88 U16.9@6479.69,3409.88 U18.3 U18.14 U19.4

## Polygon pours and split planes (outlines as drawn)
PGND on Top Layer "NONET_L-01_P-001" (solid, pour order 88): 712,1209 1525.84,1209 1620,1103.65 1620,570 1635,555 1865,555 1900,590 1900,1725 715,1725 700,1710 695,1660 695,1226
48Vo+ on Top Layer "NONET_L-01_P-001" (solid, pour order 132): 9363,1711 9799.84,1711 9823,1687.42 9823,725 9794,696 9361,696 9339,718 9339,1687
NetC1_2 on Top Layer "NONET_L-01_P-001" (solid, pour order 131): 594,887 594,1118.7 607.73,1136 1491,1136 1549,1078 1549,884 1544,879 602,879
GaN_SW1 on Top Layer "NONET_L-01_P-001" (solid, pour order 93): 1265,2735 1430,2900 2090,2900 2125,2865 2125,2640 2085,2600 1605,2600 1553,2548 1553,2308 1520,2275 1275,2275 1265,2285
PGND on Top Layer "NONET_L-01_P-001" (solid, pour order 86): 735,2443 752,2460 1034,2460 1055,2439 1055,2100 1211,1944 1588,1944 1621,1977 1621,2508 1628,2515 1875,2515 1900,2490 1900,1715 1835.29,1650.29 704.71,1650.29 695,1660 695,1800 735,1840
NetT2_1 on Top Layer "" (solid, pour order 106): 1918,3150 2095,3150 2115,3130 2115,2955 2095,2935 1920,2935 1907,2948 1907,3139
12Vs on Top Layer "NONET_L-01_P-001" (solid, remove dead copper, pour order 103): 2940,4210 4166,4210 5007.46,3368.54 6473,3368.54 6473,3113 6443.88,3083.88 4861.12,3083.88 3945,4000 2930,4000 2915,4015 2915,4185
DGND on Top Layer "NONET_L-01_P-001" (solid, pour order 34): 8286.5,3292.28 8291.5,3297.28 8827.21,3833 9101,3833 9116.5,3817.5 9116.5,152.28 9016.5,52.28 8346.5,52.28 8286.5,112.28
RTN on Top Layer "NONET_L-01_P-001" (solid, pour order 80): 20.47,2422.28 60.75,2462.56 620.2,2462.56 675.47,2407.28 675.47,2077.28 647.36,2049.17 52.68,2049.17 52.68,2050.08 20.47,2082.28
NetC2_1 on Top Layer "NONET_L-01_P-001" (solid, remove dead copper, pour order 71): 6716.5,67.28 6750.52,97.28 6750.52,1751.59 6796.5,1783.77 6796.5,1912.28 6791.5,1917.28 6625,1917.28 6215,1663.38 6215,165 6312.72,67.28
SEC_SW2 on Top Layer "NONET_L-01_P-001" (solid, pour order 52): 6896.5,1917.28 7011.5,1917.28 7067,1861.78 7067,152 6990,75 6896.5,75
SEC_SW1 on Top Layer "NONET_L-01_P-001" (solid, pour order 18): 7426.5,2777.28 7441.5,2792.28 7736.5,2792.28 7761.5,2767.28 7761.5,1962.28 7701.5,1902.28 7451.5,1902.28 7426.5,1927.28
DGND on Top Layer "NONET_L-01_P-001" (solid, pour order 26): 7126.5,2832.28 7166.5,2872.28 7329.61,2872.28 7376.5,2825.39 7376.5,1932.28 7126.5,1932.28
DGND on Top Layer "NONET_L-01_P-001" (solid, pour order 27): 7126.5,1951.71 7126.5,532.28 7366.5,532.28 7366.5,1402.28 7316.5,1452.28 7316.5,1959.02
48Vo- on Top Layer "NONET_L-01_P-001" (solid, pour order 32): 9256.5,3859 9272,3872.28 9761.5,3872.28 9811.5,3822.28 9811.5,3202.28 9776.5,3167.28 9286.5,3167.28 9256.5,3197.28
48Vo+ on Top Layer "NONET_L-01_P-001" (solid, pour order 28): 7819,2792.28 8194,2792.28 8199,2787.28 8199,74.78 8176.5,52.28 7836.5,52.28 7814,74.78 7814,1407.28 7894,1487.28 7894,1867.28 7814,1947.28 7814,2787.28
SEC_SW2 on Top Layer "NONET_L-01_P-001" (solid, pour order 24): 7431.5,1372.28 7741.5,1372.28 7761.5,1352.28 7761.5,542.28 7741.5,522.28 7431.5,522.28 7416.5,537.28 7416.5,1357.28
48Vo+ on Bottom Layer "NONET_L-01_P-001" (solid, pour order 134): 9364,1712 9797.25,1712 9823,1685.78 9823,723 9796,696 9361,696 9339,718 9339,1687
GaN_SW2 on Bottom Layer "NONET_L-01_P-001" (solid, pour order 129): 600,795 1159.76,795 1160.5,794.26 1159,792.76 1159,690 600,690 591,699 591,786
NetC1_2 on Bottom Layer "NONET_L-01_P-001" (solid, pour order 128): 1045.01,1099.99 970,1017 601,1017 593,1009 593,887 600,880 1055,880 1055,1090
PGND on Bottom Layer "NONET_L-01_P-001" (solid, pour order 119): 735,2450 745,2460 1035,2460 1087,2408 1087,2068 1210,1945 1585,1945 1640,2000 1640,2510 1645,2515 1875,2515 1900,2490 1900,1695 1857,1652 713,1652 695,1670 695,1800 735,1840
NetT2_1 on Bottom Layer "NONET_L-01_P-001" (solid, pour order 105): 2095,3150 1615,3150 1240,2775 1240,2030 1265,2005 1530,2005 1574,2049 1574,2569 1940,2935 2095,2935 2115,2955 2115,3130
NetC1_2 on Bottom Layer "NONET_L-01_P-001" (solid, pour order 98): 1545,880 1550,885 1550,1085 1475,1160 1094,1160 1035,1087.44 1035,900 1055,880
GaN_SW2 on Bottom Layer "NONET_L-01_P-001" (solid, pour order 117): 1060,780 1075,795 1535,795 1555,775 1555,573 1542,560 1268,560 1259,569 1259,626 1195,690 1085,690 1060,715
5Vs on Bottom Layer "NONET_L-01_P-001" (solid, pour order 102): 6755,3300 6784.09,3329.09 6784.09,3385.91 6484.67,3685.33 2819.23,3685.33 2797.28,3707.28 2517.42,3707.28 2495.47,3685.33 2495.47,3639.53 2495.47,3539.53 2532,3503 6511.92,3503 6714.92,3300
5Vs on Bottom Layer "" (solid, pour order 104): 2493,3539.52 2493,495.22 2511.07,474 2725,474 2765,514 2765,3428 2877.43,3540.43
HVBUS on Bottom Layer "NONET_L-01_P-001" (solid, pour order 91): 71.5,1442.28 96.5,1467.28 592.28,1467.28 712,1587 1898,1587 1990,1685 1990,2500 2015,2525 2240,2525 2265,2500 2265,585.72 2234.28,555 2005,555 1990,570 1990,940 1531.29,1228 1030.15,1228 911.08,1099 96,1099 71.5,1123.5
RTN on Bottom Layer "NONET_L-01_P-001" (solid, pour order 79): 60.75,2462.56 455.75,2462.56 620.2,2462.56 675.47,2407.28 675.47,2077.28 647.36,2049.17 53.58,2049.17 20.47,2082.28 20.47,2422.28
NetC2_1 on Bottom Layer "NONET_L-01_P-001" (solid, pour order 72): 6215,1663.38 6608,1917.28 6791.5,1917.28 6796.5,1912.28 6796.5,1783.77 6750.52,1751.59 6750.52,97.28 6716.5,67.28 6312.72,67.28 6215,165
SEC_SW2 on Bottom Layer "NONET_L-01_P-001" (solid, pour order 54): 6896.5,1917.28 7011.5,1917.28 7071.5,1857.28 7071.5,156.5 6990,75 6896.5,75
DGND on Bottom Layer "NONET_L-01_P-001" (solid, pour order 30): 7488.27,3292.28 8286.5,3292.28 8866.5,3872.28 9082.36,3872.28 9116.5,3838.15 9116.5,147.28 9021.5,52.28 7171.5,52.28 7126.5,97.28 7126.5,2971.85
48Vo- on Bottom Layer "NONET_L-01_P-001" (solid, pour order 31): 9266.5,3872.28 9761.5,3872.28 9811.5,3822.28 9811.5,3202.28 9776.5,3167.28 9286.5,3167.28 9256.5,3197.28 9256.5,3868.28
DGND on Layer 1 "NONET_L-01_P-001" (solid, pour order 39): 7421.66,3049 7542.92,3157.13 7871.31,3157.13 8505.18,3810.13 8505.18,4143.6 8238.78,4410 2599.21,4410 2490,4300.79 2490,440 2545,385 3080,385 3139,444 3139,2962.64 3185.45,3049
PGND on Layer 1 "NONET_L-01_P-001" (solid, pour order 126): 860,2312.12 860,2030 850,2020 890,1980 1200,1980 1200,2955 1093,2955 633.33,2495.33
PGND on Layer 1 "NONET_L-01_P-001" (solid, pour order 122): 1200,2390 1200,1850 920,1570 920,794 1049,665 1186,665 1204,647 1204,574 1189,559 930,559 785,704 785,1975
PGND on Layer 1 "NONET_L-01_P-001" (solid, pour order 61): 11.5,3926.5 452.28,4367.28 2076.5,4367.28 2206.5,4237.28 2206.5,3206.5 2190,3190 1585,3190 885,2490 93.96,2490 11.5,2612.28
RTN on Layer 1 "NONET_L-01_P-001" (solid, pour order 81): 60.75,2462.56 620.2,2462.56 675.47,2407.28 675.47,2077.28 647.36,2049.17 53.58,2049.17 20.47,2082.28 20.47,2422.28
DGND on Layer 1 "NONET_L-01_P-001" (solid, pour order 42): 8225.47,4410 9292.76,4410 9340.47,4362.28 9340.47,3932.28 9280.47,3872.28 8571.5,3872.28 8225.47,3526.26
48Vo+ on Layer 1 "NONET_L-01_P-001" (solid, pour order 35): 7846.5,52.28 9247.28,52.28 9821.5,555 9821.5,1666.23 9285.47,1959.68 9285.47,3698.31 9151.5,3832.28 8606.5,3832.28 8296.5,3522.28 7846.5,3036.2
DGND on Layer 1 "NONET_L-01_P-001" (solid, pour order 67): 5487.7,2439.56 5519,2408.26 5519,926.22 5462.34,869.56 5087.34,869.56 5052.34,904.56 5052.34,2405.08 5086.82,2439.56
PGND on Layer 1 "NONET_L-01_P-001" (solid, remove dead copper, pour order 65): 3888,2296.33 3997.93,2406.26 4397.93,2406.26 4452.93,2406.26 4617.93,2241.26 4617.93,946.26 4542.93,871.26 3947.93,871.26 3888,931.19
SEC_SW2 on Layer 3 "NONET_L-01_P-001" (solid, pour order 55): 6896.5,52.28 7101.43,52.28 7475,52.28 7745,251.61 7745,1351 7723.72,1372.28 7402,1372.28 7101.5,1590.71 7101.5,1827.28 7014.78,1914 6896.5,1914
5Vp on Layer 3 "NONET_L-01_P-001" (solid, pour order 118): 2100.91,3297.99 2053.41,3265 1512,3265 1080,2833 1080,2134 798,1852 798,760 1082,476 1153,476 1158,481 1158,538 1139,557 905,791 905,1805 1180,2080 1180,2780 1590,3190 2080,3190 2100.91,3210.91
48Vo+ on Layer 3 "NONET_L-01_P-001" (solid, pour order 37): 7855,52.28 9247.28,52.28 9821.5,555 9821.5,1667.28 9285.47,1960.72 9285.47,3698.31 9151.5,3832.28 8606.5,3832.28 8296.5,3522.28 7855,3045.39
5Vp on Layer 3 "NONET_L-01_P-001" (solid, pour order 109): 2080,3190 2174.63,3190 2200,3217.69 2200,3986.27 2171.27,4015 1860,4015 1860,3956 1874.07,3941.93 2028.56,3941.93 2077.28,3893.2 2077.28,3192.72
SEC_SW1 on Layer 3 "NONET_L-01_P-001" (solid, pour order 111): 6777,1952 7657,1952 7680,1975 7680,2685 7496,2869 6384,2869 6190,2675 6190,1930 6245,1875 6700,1875
12Vp on Layer 2 "NONET_L-01_P-001" (solid, pour order 127): 1559,3967 1691,3967 1728,3930 1728,3782 1198,3252 1198,2373 1108,2373 1083.19,2397.81 1083.19,3291.19 1528,3736 1528,3936
12Vp on Layer 2 "NONET_L-01_P-001" (solid, pour order 124): 1212,481 1198,467 1064,467 955,576 955,1279.29 1083,1407.29 1083,2450 1140,2450 1199,2391 1199,1364 1045,1210 1045,623 1110,558 1199,558 1212,545
NetT2_1 on Layer 2 "NONET_L-01_P-001" (solid, pour order 107): 2115,3130 2095,3150 1615,3150 1240,2775 1240,2030 1265,2005 1530,2005 1580,2055 1580,2575 1940,2935 2095,2935 2115,2955
DGND on Layer 2 "NONET_L-01_P-001" (solid, remove dead copper, pour order 44): 2490,440 2490,4300.79 2598.21,4409 9293.76,4409 9340.47,4362.28 9340.47,3932.28 9280.47,3872.28 8611.5,3872.28 8056.5,3317.28 7462.42,3317.28 7161.39,3047 3188.55,3047 3139,2964.41 3139,444 3080,385 2545,385
NetC2_1 on Layer 2 "NONET_L-01_P-001" (solid, pour order 74): 6583.65,1917.28 6791.5,1917.28 6796.5,1912.28 6796.5,1783.77 6750.52,1751.59 6750.52,97.28 6720.52,67.28 6312.72,67.28 6215,165 6215,1663.38
48Vo- on Layer 2 "NONET_L-01_P-001" (solid, pour order 62): 9256.5,3797.28 9296.5,3837.28 9796.5,3837.28 9811.5,3822.28 9811.5,3202.28 9776.5,3167.28 9286.5,3167.28 9256.5,3197.28 9256.5,3792.28
DGND on Layer 2 "NONET_L-01_P-001" (solid, pour order 36): 7126.5,2972.28 7487.79,3292.28 8286.5,3292.28 8826.5,3832.28 9073.15,3832.28 9116.5,3788.94 9116.5,152.28 9016.5,52.28 7171.5,52.28 7126.5,97.28
DGND on Layer 4 "NONET_L-01_P-001" (solid, remove dead copper, pour order 40): 8450.47,3722.28 8690.47,3962.28 9340.47,3962.28 9340.47,145.47 9247.28,52.28 8450.47,52.28
DGND on Layer 4 "NONET_L-01_P-001" (solid, pour order 41): 8250.47,4397.28 9305.47,4397.28 9340.47,4362.28 9340.47,3932.28 9284.54,3876.35 8616.51,3876.35 8250.47,3510.31
GaN_SW2 on Layer 4 "NONET_L-01_P-001" (solid, pour order 130): 591,791 596,796 1095,796 1095,671 617,671 591,697
SEC_SW1 on Layer 4 "NONET_L-01_P-001" (solid, pour order 110): 6700,1875 6777.97,1952.97 7072.99,1953.03 7073.03,1952.97 7657.97,1952.97 7680,1975 7680,2685 7495,2870 6385,2870 6190,2675 6190,1930 6245,1875
GaN_SW1 on Layer 4 "NONET_L-01_P-001" (solid, pour order 92): 1520,2275 1275,2275 1260,2290 1260,2729.17 1435,2900 2090,2900 2125,2865 2125,2640 2085,2600 1605,2600 1555,2550 1555,2310
GaN_SW2 on Layer 4 "NONET_L-01_P-001" (solid, pour order 114): 1060,780 1076,796 1534,796 1555,775 1555,580 1535,560 1250,560 1244,566 1244,641 1214,671 1090,671 1060,701
PGND on Layer 4 "NONET_L-01_P-001" (solid, pour order 120): 735,2450 745,2460 950,2460 1175.65,2234.35 1175.65,2029.35 1240,1965 1580,1965 1620,2005 1620,2510.5 1624.5,2515 1875,2515 1900,2490 1900,585 1870,555 1635,555 1620,570 1620,1085 1563.43,1155.02 1175.65,1155.02 744.98,1155.02 695,1205 695,1800 735,1840
SEC_SW2 on Layer 4 "NONET_L-01_P-001" (solid, pour order 53): 6896.5,52.28 7490.12,52.28 7744,239 7744,1355 7726.72,1372.28 7401.5,1372.28 7101.5,1590.71 7101.5,1827.28 7012.78,1916 6896.5,1916
DGND on Layer 4 "NONET_L-01_P-001" (solid, pour order 83): 7895.31,3157.13 8370.63,3157.13 8475.47,3052.28 8555.47,3132.28 8555.47,3772.28 7890.47,3772.28 7880.47,3762.28 7880.47,3164.9
DGND on Layer 4 "NONET_L-01_P-001" (solid, pour order 38): 7420.15,3047.59 7542.15,3157.13 7895.31,3157.13 8506.5,3768.31 8506.5,4142.28 8251.5,4397.28 2586.5,4397.28 2490,4300.79 2490,2358.78 2490,440 2545,385 3080,385 3140,445 3140,2966.08 3194.72,3057.28
PGND on Layer 4 "NONET_L-01_P-001" (solid, pour order 76): 11.5,3936.5 442.28,4367.28 2076.5,4367.28 2206.5,4237.28 2206.5,3206.5 2190,3190 1585,3190 885,2490 93.96,2490 11.5,2612.28
DGND on Layer 4 "NONET_L-01_P-001" (solid, pour order 68): 5052.34,2405.08 5086.82,2439.56 5487.7,2439.56 5519,2408.26 5519,926.22 5462.34,869.56 5087.34,869.56 5052.34,904.56
PGND on Layer 4 "NONET_L-01_P-001" (solid, pour order 66): 3888,2296.33 3997.93,2406.26 4452.93,2406.26 4617.93,2241.26 4617.93,946.26 4542.93,871.26 3947.93,871.26 3888,931.19
no net on Top Solder "NONET_L-01_P-001" (solid): 9429,1424 9823,1424 9823,1031 9429,1031
no net on Bottom Solder "NONET_L-01_P-001" (solid): 9429,1425.5 9823,1425.5 9823,1032.5 9429,1032.5

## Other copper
Top Layer:
  pour cut-out: 8632.77,322.11 ccw(c8632.77,379.84) 8690.5,379.84 ccw(c8630.41,382.21) 8630.41,442.34 ccw(c8630.41,382.21)
  pour cut-out: 8632.91,995.28 ccw(c8632.92,1053.01) 8690.64,1053.01 ccw(c8630.55,1055.37) 8630.55,1115.51 ccw(c8630.55,1055.37)
  pour cut-out: 8633.07,1662.94 ccw(c8633.07,1720.67) 8690.8,1720.67 ccw(c8630.71,1723.03) 8630.71,1783.17 ccw(c8630.71,1723.03)
  pour cut-out: 8632.93,2343.27 ccw(c8632.93,2401) 8690.66,2401 ccw(c8630.57,2403.36) 8630.57,2463.5 ccw(c8630.57,2403.36)
  pour cut-out: 8632.92,3017.92 ccw(c8632.92,3075.65) 8690.65,3075.65 ccw(c8630.56,3078.01) 8630.56,3138.15 ccw(c8630.56,3078.01)
  pour cut-out: 1676,1574 1847,1574 1847,1403 1676,1403
  pour cut-out: 919,1567 1090,1567 1090,1396 919,1396
Bottom Layer:
  pour cut-out: 8570.61,381.37 ccw(c8630.75,381.37) 8630.75,321.23 ccw(c8630.75,381.37) 8690.89,381.37 ccw(c8630.75,381.37) 8630.75,441.51 ccw(c8630.75,381.37)
  pour cut-out: 8570.52,1054.41 ccw(c8630.66,1054.41) 8630.66,994.27 ccw(c8630.66,1054.41) 8690.8,1054.41 ccw(c8630.66,1054.41) 8630.66,1114.55 ccw(c8630.66,1054.41)
  pour cut-out: 8572.39,2403.52 ccw(c8632.52,2403.52) 8632.52,2343.39 ccw(c8632.52,2403.52) 8692.66,2403.52 ccw(c8632.52,2403.52) 8632.52,2463.66 ccw(c8632.52,2403.52)
  pour cut-out: 8570.39,1723.52 ccw(c8630.52,1723.52) 8630.52,1663.39 ccw(c8630.52,1723.52) 8690.66,1723.52 ccw(c8630.52,1723.52) 8630.52,1783.66 ccw(c8630.52,1723.52)
  pour cut-out: 8571.32,3077.28 ccw(c8631.46,3077.28) 8631.46,3017.15 ccw(c8631.46,3077.28) 8691.59,3077.28 ccw(c8631.46,3077.28) 8631.46,3137.42 ccw(c8631.46,3077.28)
  region net 5Vs: 6743,3426 6914,3426 6922,3418 6922,3311 6911,3300 6755,3300 6755,3305 6743,3317

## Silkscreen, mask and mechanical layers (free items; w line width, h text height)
Top Solder:
  region: 9437,3716 9813,3716 9813,3320 9437,3320
Bottom Solder:
  region: 9446,3718 9811.5,3718 9811.5,3322 9446,3322
Mechanical 1:
  lines w5: -3,-18 -3,4427 9844,4427 9844,-18 -3,-18
  lines w10: 3183.6,1670.22 3860,1670.22 ; 3183.7,1552.11 3535.6,1552.11 ; 3185,2146.21 3861.4,2146.21 ; 3185.09,1168.45 3860.49,1168.34 ; 3185.1,2028.1 3537,2028.1 ; 3185.19,1050.34 3537.09,1050.34 ; 3530,1552.11 3860,1552.11 ; 3531.4,2028.1 3861.4,2028.1 ; 3531.49,1050.34 3860,1050 ; 3860,785 5541.49,785 ; 3860,787.51 3860,2550 4310,2550 4310,2880 ; 4311,2550 4428,2550 ; 4428.11,2885 4428.11,2550 5542,2550 ; 4972.1,2550.6 4972.1,2880.6 ; 4973.1,2550.6 5090.1,2550.6 ; 5090.21,2550.6 5090.21,2885.6 ; 5541.41,1634.88 6119.99,1635.06 ; 5541.51,1516.77 5893.41,1516.77 ; 5542,785 5542,2549.05 ; 5542.81,2110.87 6119.99,2110.87 ; 5542.9,1133.11 6119.99,1133.44 ; 5542.91,1992.76 5894.81,1992.76 ; 5543,1015 5894.9,1015 ; 5887.81,1516.77 6119.99,1516.77 ; 5889.21,1992.76 6119.99,1992.76 ; 5889.3,1015 6119.99,1015 ; 5542,2549.05 5542,2549.05 ; 3185,235 3185,2885 6120,2885 6120,235 3185,235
